# 3066MNPIRH register map
File version: 1.0
Registers are 32-bit, access per field, reset 0x0 unless marked. A register's access mark holds for its fields unless they carry their own. Offsets are from the block's base; [hi:lo] are bit positions; {n}, {i} and the like mark numbered series.

## APT0 — APT0 peripheral interface
Base 0x14A00000
Same registers: APT{n} {0x14A00000+0x1000*n} (n=1..8)
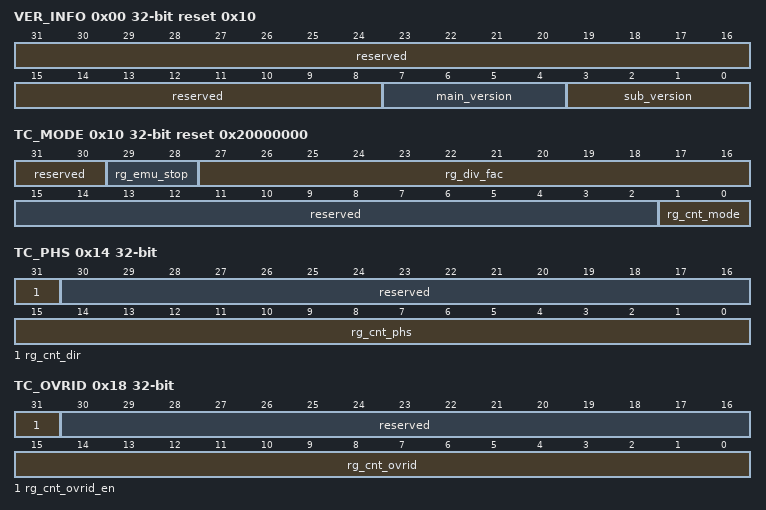
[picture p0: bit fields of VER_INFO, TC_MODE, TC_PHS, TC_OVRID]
0x00 VER_INFO ro reset 0x10 — VER_INFO为版本信息寄存器。
  [31:8] reserved — 保留。
  [7:4] main_version — 主版本号。
  [3:0] sub_version — 子版本号。
0x10 TC_MODE reset 0x20000000 — TC_MODE为计数模式寄存器。
  [31:30] reserved ro — 保留。
  [29:28] rg_emu_stop rw — CPU debug模式，APT停止的方式。注意，如果停止APT，那么在CPU debug模式下，整个APT都会停止工作，包括输出控制功能。 0X：不停止； 10：停止分频计数器（DIVCNT）和时基计数器（TCCNT）； 11：停止APT。
  [27:16] rg_div_fac rw — 分频系数。 分频倍数 = 分频系数 +1。
  [15:2] reserved ro — 保留。
  [1:0] rg_cnt_mode rw — 时基计数器（TCCNT）的工作模式。 00：递增计数； 01：递减计数； 10：先增后减计数； 11：冻结。
0x14 TC_PHS — TC_PHS为计数相位控制寄存器。
  [31] rg_cnt_dir rw — 当APTCNTSYNC有效时，更新时基计数器（TCCNT）的计数方向，仅在先增后减计数模式有效。 0：递减； 1：递增。
  [30:16] reserved ro — 保留。
  [15:0] rg_cnt_phs rw — 当APTCNTSYNC有效时，更新时基计数器（TCCNT）的计数值。
0x18 TC_OVRID — TC_OVRID为计数器初始化寄存器。
  [31] rg_cnt_ovrid_en rw write-1-clears — 时基计数器（TCCNT）和分频计数器（DIVCNT）的初始化使能。 0：无效； 1：初始化时基计数器（TCCNT）和分频计数器（DIVCNT）的计数值。
  [30:16] reserved ro — 保留。
  [15:0] rg_cnt_ovrid rw — 初始化时基计数器（TCCNT）的计数值。
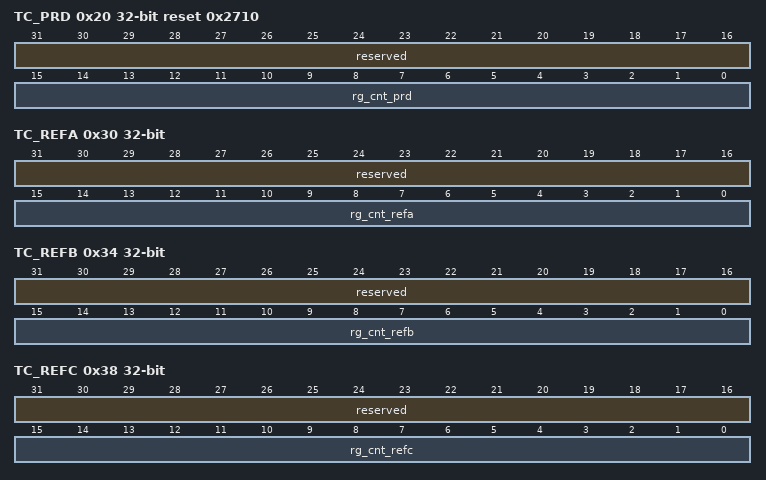
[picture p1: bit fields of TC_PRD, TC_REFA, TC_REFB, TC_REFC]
0x20 TC_PRD reset 0x2710 — TC_PRD为计数周期寄存器。
  [31:16] reserved ro — 保留。
  [15:0] rg_cnt_prd rw — 时基计数器（TCCNT）的计数周期。
0x30 TC_REFA — TC_REFA为计数参考值A寄存器。
  [31:16] reserved ro — 保留。
  [15:0] rg_cnt_refa rw — 时基计数器（TCCNT）的参考值A，应当小于或等于计数周期。
0x34 TC_REFB — TC_REFB为计数参考值B寄存器。
  [31:16] reserved ro — 保留。
  [15:0] rg_cnt_refb rw — 时基计数器（TCCNT）的参考值B，应当小于或等于计数周期。
0x38 TC_REFC — TC_REFC为计数参考值C寄存器。
  [31:16] reserved ro — 保留。
  [15:0] rg_cnt_refc rw — 时基计数器（TCCNT）的参考值C，应当小于或等于计数周期。
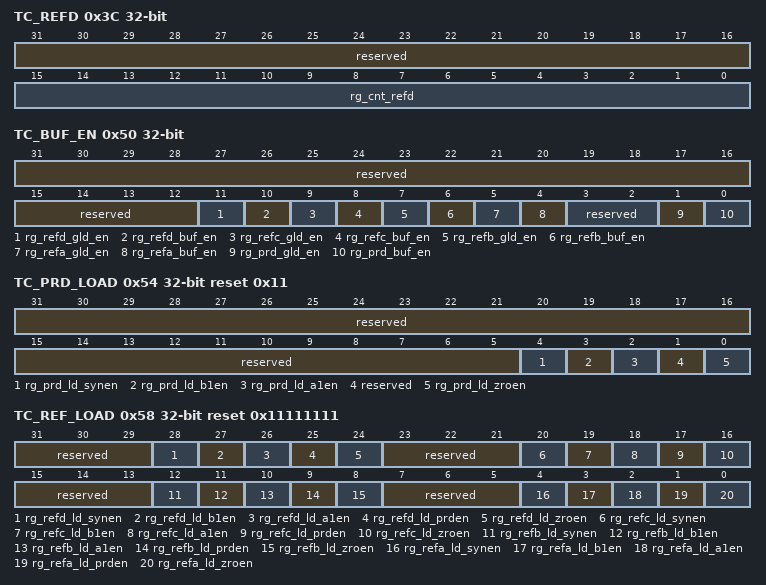
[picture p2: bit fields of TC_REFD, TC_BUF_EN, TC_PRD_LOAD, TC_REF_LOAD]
0x3C TC_REFD — TC_REFD为计数参考值D寄存器。
  [31:16] reserved ro — 保留。
  [15:0] rg_cnt_refd rw — 时基计数器（TCCNT）的参考值D，应当小于或等于计数周期。
0x50 TC_BUF_EN — TC_BUF_EN为计数器缓存使能寄存器。
  [31:12] reserved ro — 保留。
  [11] rg_refd_gld_en rw — TC_REFD寄存器的全局加载使能。 0：不使能； 1：使能。
  [10] rg_refd_buf_en rw — TC_REFD寄存器的缓存使能。 0：不使能； 1：使能。
  [9] rg_refc_gld_en rw — TC_REFC寄存器的全局加载使能。 0：不使能； 1：使能。
  [8] rg_refc_buf_en rw — TC_REFC寄存器的缓存使能。 0：不使能； 1：使能。
  [7] rg_refb_gld_en rw — TC_REFB寄存器的全局加载使能。 0：不使能； 1：使能。
  [6] rg_refb_buf_en rw — TC_REFB寄存器的缓存使能。 0：不使能； 1：使能。
  [5] rg_refa_gld_en rw — TC_REFA寄存器的全局加载使能。 0：不使能； 1：使能。
  [4] rg_refa_buf_en rw — TC_REFA寄存器的缓存使能。 0：不使能； 1：使能。
  [3:2] reserved ro — 保留。
  [1] rg_prd_gld_en rw — TC_PRD寄存器的全局加载使能。 0：不使能； 1：使能。
  [0] rg_prd_buf_en rw — TC_PRD寄存器的缓存使能。 0：不使能； 1：使能。
0x54 TC_PRD_LOAD reset 0x11 — TC_PRD_LOAD为计数周期寄存器独立加载触发信号选择寄存器。
  [31:5] reserved ro — 保留。
  [4] rg_prd_ld_synen rw — 选择APTxSYNCI有效时，是否使能TC_PRD寄存器的独立加载。 0：不使能； 1：使能。
  [3] rg_prd_ld_b1en rw — 选择EMEVTB1有效时，是否使能TC_PRD寄存器的独立加载。 0：不使能； 1：使能。
  [2] rg_prd_ld_a1en rw — 选择EMEVTA1有效时，是否使能TC_PRD寄存器的独立加载。 0：不使能； 1：使能。
  [1] reserved ro — 保留。
  [0] rg_prd_ld_zroen rw — 选择CNT_ZERO有效时，是否使能TC_PRD寄存器的独立加载。 0：不使能； 1：使能。
0x58 TC_REF_LOAD reset 0x11111111 — TC_REF_LOAD为计数参考值寄存器独立加载触发信号选择寄存器。
  [31:29] reserved ro — 保留。
  [28] rg_refd_ld_synen rw — 选择APTxSYNCI有效时，是否使能TC_REFD寄存器的独立加载。 0：不使能； 1：使能。
  [27] rg_refd_ld_b1en rw — 选择EMEVTB1有效时，是否使能TC_REFD寄存器的独立加载。 0：不使能； 1：使能。
  [26] rg_refd_ld_a1en rw — 选择EMEVTA1有效时，是否使能TC_REFD寄存器的独立加载。 0：不使能； 1：使能。
  [25] rg_refd_ld_prden rw — 选择CNT_PRD有效时，是否使能TC_REFD寄存器的独立加载。 0：不使能； 1：使能。
  [24] rg_refd_ld_zroen rw — 选择CNT_ZERO有效时，是否使能TC_REFD寄存器的独立加载。 0：不使能； 1：使能。
  [23:21] reserved ro — 保留。
  [20] rg_refc_ld_synen rw — 选择APTxSYNCI有效时，是否使能TC_REFC寄存器的独立加载。 0：不使能； 1：使能。
  [19] rg_refc_ld_b1en rw — 选择EMEVTB1有效时，是否使能TC_REFC寄存器的独立加载。 0：不使能； 1：使能。
  [18] rg_refc_ld_a1en rw — 选择EMEVTA1有效时，是否使能TC_REFC寄存器的独立加载。 0：不使能； 1：使能。
  [17] rg_refc_ld_prden rw — 选择CNT_PRD有效时，是否使能TC_REFC寄存器的独立加载。 0：不使能； 1：使能。
  [16] rg_refc_ld_zroen rw — 选择CNT_ZERO有效时，是否使能TC_REFC寄存器的独立加载。 0：不使能； 1：使能。
  [15:13] reserved ro — 保留。
  [12] rg_refb_ld_synen rw — 选择APTxSYNCI有效时，是否使能TC_REFB寄存器的独立加载。 0：不使能； 1：使能。
  [11] rg_refb_ld_b1en rw — 选择EMEVTB1有效时，是否使能TC_REFB寄存器的独立加载。 0：不使能； 1：使能。
  [10] rg_refb_ld_a1en rw — 选择EMEVTA1有效时，是否使能TC_REFB寄存器的独立加载。 0：不使能； 1：使能。
  [9] rg_refb_ld_prden rw — 选择CNT_PRD有效时，是否使能TC_REFB寄存器的独立加载。 0：不使能； 1：使能。
  [8] rg_refb_ld_zroen rw — 选择CNT_ZERO有效时，是否使能TC_REFB寄存器的独立加载。 0：不使能； 1：使能。
  [7:5] reserved ro — 保留。
  [4] rg_refa_ld_synen rw — 选择APTxSYNCI有效时，是否使能TC_REFA寄存器的独立加载。 0：不使能； 1：使能。
  [3] rg_refa_ld_b1en rw — 选择EMEVTB1有效时，是否使能TC_REFA寄存器的独立加载。 0：不使能； 1：使能。
  [2] rg_refa_ld_a1en rw — 选择EMEVTA1有效时，是否使能TC_REFA寄存器的独立加载。 0：不使能； 1：使能。
  [1] rg_refa_ld_prden rw — 选择CNT_PRD有效时，是否使能TC_REFA寄存器的独立加载。 0：不使能； 1：使能。
  [0] rg_refa_ld_zroen rw — 选择CNT_ZERO有效时，是否使能TC_REFA寄存器的独立加载。 0：不使能； 1：使能。
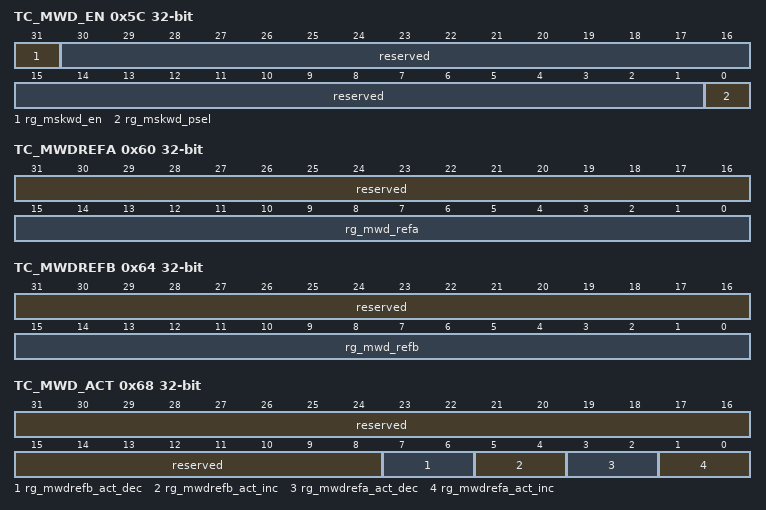
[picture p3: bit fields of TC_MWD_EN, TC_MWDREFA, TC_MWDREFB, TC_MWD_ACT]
0x5C TC_MWD_EN — TC_MWD_EN为屏蔽窗口使能寄存器。
  [31] rg_mskwd_en rw — 屏蔽窗口使能位。 0：不使能； 1：使能。
  [30:1] reserved ro — 保留。
  [0] rg_mskwd_psel rw — MASK_WD_POL的源选择。 0：MASK_WD_POL的源是MASK_WD取反后的波形； 1：MASK_WD_POL的源是MASK_WD。
0x60 TC_MWDREFA — TC_MWDREFA为屏蔽窗口参考值A寄存器。
  [31:16] reserved ro — 保留。
  [15:0] rg_mwd_refa rw — 屏蔽窗口参考值A，应当小于或等于计数周期。
0x64 TC_MWDREFB — TC_MWDREFB为屏蔽窗口参考值B寄存器。
  [31:16] reserved ro — 保留。
  [15:0] rg_mwd_refb rw — 屏蔽窗口参考值B，应当小于或等于计数周期。
0x68 TC_MWD_ACT — TC_MWD_ACT为MASK_WD动作寄存器。
  [31:8] reserved ro — 保留。
  [7:6] rg_mwdrefb_act_dec rw — CNT_MWDREFB有效且TCCNT计数方向递减时，MASK_WD的动作。 00：无影响； 01：置为低电平； 10：置为高电平； 11：翻转电平。
  [5:4] rg_mwdrefb_act_inc rw — CNT_MWDREFB有效且TCCNT计数方向递增时，MASK_WD的动作。 00：无影响； 01：置为低电平； 10：置为高电平； 11：翻转电平。
  [3:2] rg_mwdrefa_act_dec rw — CNT_MWDREFA有效且TCCNT计数方向递减时，MASK_WD的动作。 00：无影响； 01：置为低电平； 10：置为高电平； 11：翻转电平。
  [1:0] rg_mwdrefa_act_inc rw — CNT_MWDREFA有效且TCCNT计数方向递增时，MASK_WD的动作。 00：无影响； 01：置为低电平； 10：置为高电平； 11：翻转电平。
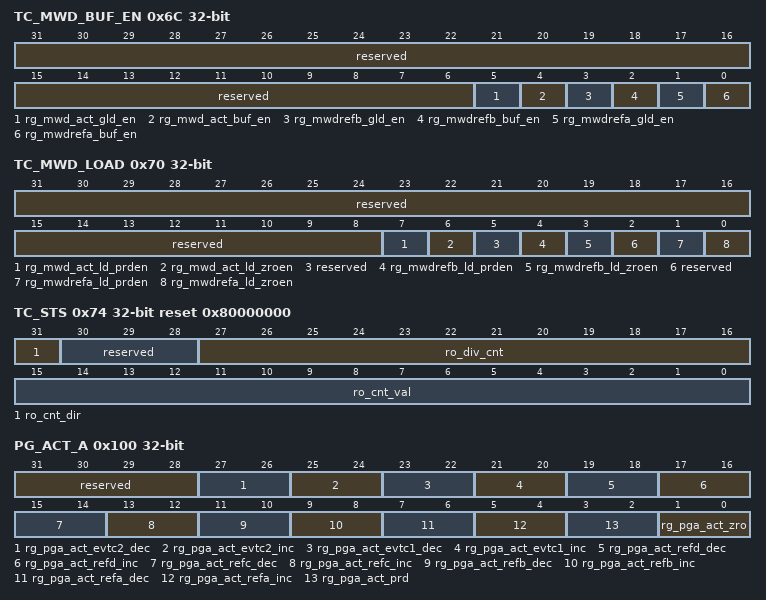
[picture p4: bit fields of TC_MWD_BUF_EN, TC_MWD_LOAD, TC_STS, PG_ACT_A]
0x6C TC_MWD_BUF_EN — TC_MWD_BUF_EN为屏蔽窗口缓存使能寄存器。
  [31:6] reserved ro — 保留。
  [5] rg_mwd_act_gld_en rw — TC_MWD_ACT寄存器的全局加载使能。 0：不使能； 1：使能。
  [4] rg_mwd_act_buf_en rw — TC_MWD_ACT寄存器的缓存使能。 0：不使能； 1：使能。
  [3] rg_mwdrefb_gld_en rw — TC_MWDREFB寄存器的全局加载使能。 0：不使能； 1：使能。
  [2] rg_mwdrefb_buf_en rw — TC_MWDREFB寄存器的缓存使能。 0：不使能； 1：使能。
  [1] rg_mwdrefa_gld_en rw — TC_MWDREFA寄存器的全局加载使能。 0：不使能； 1：使能。
  [0] rg_mwdrefa_buf_en rw — TC_MWDREFA寄存器的缓存使能。 0：不使能； 1：使能。
0x70 TC_MWD_LOAD — TC_MWD_LOAD为屏蔽窗口寄存器独立加载触发信号选择寄存器。
  [31:8] reserved ro — 保留。
  [7] rg_mwd_act_ld_prden rw — 选择CNT_PRD有效时，是否使能TC_MWD_ACT寄存器的独立加载。 0：不使能； 1：使能。
  [6] rg_mwd_act_ld_zroen rw — 选择CNT_ZERO有效时，是否使能TC_MWD_ACT寄存器的独立加载。 0：不使能； 1：使能。
  [5] reserved ro — 保留。
  [4] rg_mwdrefb_ld_prden rw — 选择CNT_PRD有效时，是否使能TC_MWDREFB寄存器的独立加载。 0：不使能； 1：使能。
  [3] rg_mwdrefb_ld_zroen rw — 选择CNT_ZERO有效时，是否使能TC_MWDREFB寄存器的独立加载。 0：不使能； 1：使能。
  [2] reserved ro — 保留。
  [1] rg_mwdrefa_ld_prden rw — 选择CNT_PRD有效时，是否使能TC_MWDREFA寄存器的独立加载。 0：不使能； 1：使能。
  [0] rg_mwdrefa_ld_zroen rw — 选择CNT_ZERO有效时，是否使能TC_MWDREFA寄存器的独立加载。 0：不使能； 1：使能。
0x74 TC_STS ro reset 0x80000000 — TC_STS为计数状态寄存器。
  [31] ro_cnt_dir — 时基计数器（TCCNT）的当前计数方向。 0：递减计数； 1：递增计数。
  [30:28] reserved — 保留。
  [27:16] ro_div_cnt — 分频计数器（DIVCNT）的当前计数值。
  [15:0] ro_cnt_val — 时基计数器（TCCNT）的当前计数值。
0x100 PG_ACT_A — PG_ACT_A为PG_PWMA动作配置寄存器。
  [31:28] reserved ro — 保留。
  [27:26] rg_pga_act_evtc2_dec rw — AEVTC2有效且TCCNT计数方向递减时，PG_PWMA的动作。 00：无影响； 01：置为低电平； 10：置为高电平； 11：翻转电平。
  [25:24] rg_pga_act_evtc2_inc rw — AEVTC2有效且TCCNT计数方向递增时，PG_PWMA的动作。 00：无影响； 01：置为低电平； 10：置为高电平； 11：翻转电平。
  [23:22] rg_pga_act_evtc1_dec rw — AEVTC1有效且TCCNT计数方向递减时，PG_PWMA的动作。 00：无影响； 01：置为低电平； 10：置为高电平； 11：翻转电平。
  [21:20] rg_pga_act_evtc1_inc rw — AEVTC1有效且TCCNT计数方向递增时，PG_PWMA的动作。 00：无影响； 01：置为低电平； 10：置为高电平； 11：翻转电平。
  [19:18] rg_pga_act_refd_dec rw — CNT_REFD有效且TCCNT计数方向递减时，PG_PWMA的动作。 00：无影响； 01：置为低电平； 10：置为高电平； 11：翻转电平。
  [17:16] rg_pga_act_refd_inc rw — CNT_REFD有效且TCCNT计数方向递增时，PG_PWMA的动作。 00：无影响； 01：置为低电平； 10：置为高电平； 11：翻转电平。
  [15:14] rg_pga_act_refc_dec rw — CNT_REFC有效且TCCNT计数方向递减时，PG_PWMA的动作。 00：无影响； 01：置为低电平； 10：置为高电平； 11：翻转电平。
  [13:12] rg_pga_act_refc_inc rw — CNT_REFC有效且TCCNT计数方向递增时，PG_PWMA的动作。 00：无影响； 01：置为低电平； 10：置为高电平； 11：翻转电平。
  [11:10] rg_pga_act_refb_dec rw — CNT_REFB有效且TCCNT计数方向递减时，PG_PWMA的动作。 00：无影响； 01：置为低电平； 10：置为高电平； 11：翻转电平。
  [9:8] rg_pga_act_refb_inc rw — CNT_REFB有效且TCCNT计数方向递增时，PG_PWMA的动作。 00：无影响； 01：置为低电平； 10：置为高电平； 11：翻转电平。
  [7:6] rg_pga_act_refa_dec rw — CNT_REFA有效且TCCNT计数方向递减时，PG_PWMA的动作。 00：无影响； 01：置为低电平； 10：置为高电平； 11：翻转电平。
  [5:4] rg_pga_act_refa_inc rw — CNT_REFA有效且TCCNT计数方向递增时，PG_PWMA的动作。 00：无影响； 01：置为低电平； 10：置为高电平； 11：翻转电平。
  [3:2] rg_pga_act_prd rw — CNT_PRD有效时，PG_PWMA的动作。 00：无影响； 01：置为低电平； 10：置为高电平； 11：翻转电平。
  [1:0] rg_pga_act_zro rw — CNT_ZERO有效时，PG_PWMA的动作。 00：无影响； 01：置为低电平； 10：置为高电平； 11：翻转电平。
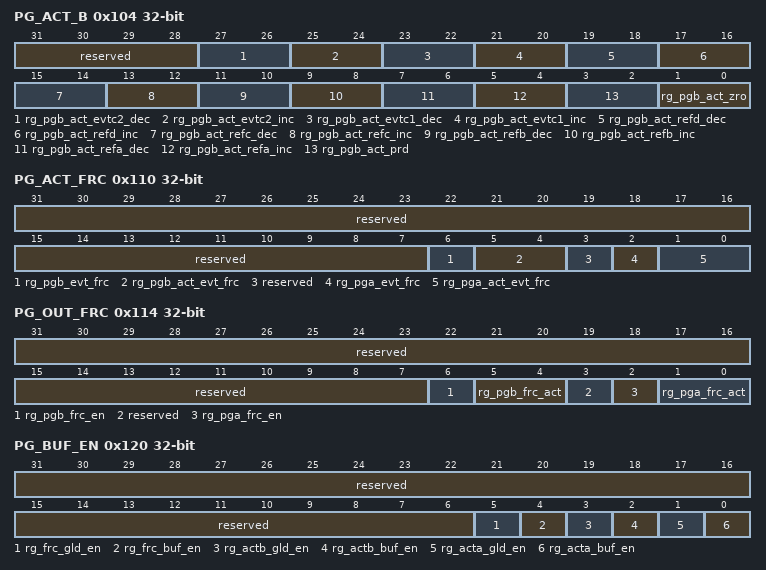
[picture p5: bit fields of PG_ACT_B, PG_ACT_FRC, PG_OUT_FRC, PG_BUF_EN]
0x104 PG_ACT_B — PG_ACT_B为PG_PWMB动作配置寄存器。
  [31:28] reserved ro — 保留。
  [27:26] rg_pgb_act_evtc2_dec rw — BEVTC2有效且TCCNT计数方向递减时，PG_PWMB的动作。 00：无影响； 01：置为低电平； 10：置为高电平； 11：翻转电平。
  [25:24] rg_pgb_act_evtc2_inc rw — BEVTC2有效且TCCNT计数方向递增时，PG_PWMB的动作。 00：无影响； 01：置为低电平； 10：置为高电平； 11：翻转电平。
  [23:22] rg_pgb_act_evtc1_dec rw — BEVTC1有效且TCCNT计数方向递减时，PG_PWMB的动作。 00：无影响； 01：置为低电平； 10：置为高电平； 11：翻转电平。
  [21:20] rg_pgb_act_evtc1_inc rw — BEVTC1有效且TCCNT计数方向递增时，PG_PWMB的动作。 00：无影响； 01：置为低电平； 10：置为高电平； 11：翻转电平。
  [19:18] rg_pgb_act_refd_dec rw — CNT_REFD有效且TCCNT计数方向递减时，PG_PWMB的动作。 00：无影响； 01：置为低电平； 10：置为高电平； 11：翻转电平。
  [17:16] rg_pgb_act_refd_inc rw — CNT_REFD有效且TCCNT计数方向递增时，PG_PWMB的动作。 00：无影响； 01：置为低电平； 10：置为高电平； 11：翻转电平。
  [15:14] rg_pgb_act_refc_dec rw — CNT_REFC有效且TCCNT计数方向递减时，PG_PWMB的动作。 00：无影响； 01：置为低电平； 10：置为高电平； 11：翻转电平。
  [13:12] rg_pgb_act_refc_inc rw — CNT_REFC有效且TCCNT计数方向递增时，PG_PWMB的动作。 00：无影响； 01：置为低电平； 10：置为高电平； 11：翻转电平。
  [11:10] rg_pgb_act_refb_dec rw — CNT_REFB有效且TCCNT计数方向递减时，PG_PWMB的动作。 00：无影响； 01：置为低电平； 10：置为高电平； 11：翻转电平。
  [9:8] rg_pgb_act_refb_inc rw — CNT_REFB有效且TCCNT计数方向递增时，PG_PWMB的动作。 00：无影响； 01：置为低电平； 10：置为高电平； 11：翻转电平。
  [7:6] rg_pgb_act_refa_dec rw — CNT_REFA有效且TCCNT计数方向递减时，PG_PWMB的动作。 00：无影响； 01：置为低电平； 10：置为高电平； 11：翻转电平。
  [5:4] rg_pgb_act_refa_inc rw — CNT_REFA有效且TCCNT计数方向递增时，PG_PWMB的动作。 00：无影响； 01：置为低电平； 10：置为高电平； 11：翻转电平。
  [3:2] rg_pgb_act_prd rw — CNT_PRD有效时，PG_PWMB的动作。 00：无影响； 01：置为低电平； 10：置为高电平； 11：翻转电平。
  [1:0] rg_pgb_act_zro rw — CNT_ZERO有效时，PG_PWMB的动作。 00：无影响； 01：置为低电平； 10：置为高电平； 11：翻转电平。
0x110 PG_ACT_FRC — PG_ACT_FRC为强制动作配置寄存器。
  [31:7] reserved ro — 保留。
  [6] rg_pgb_evt_frc rw write-1-clears — 软件强制PG_PWMB动作，每次写1产生一次PG_PWMB动作，然后自动清零。 0：写0无效； 1：写1有效。
  [5:4] rg_pgb_act_evt_frc rw — 软件强制PG_PWMB动作有效时，PG_PWMB的动作。 00：无影响； 01：置为低电平； 10：置为高电平； 11：翻转电平。
  [3] reserved ro — 保留。
  [2] rg_pga_evt_frc rw write-1-clears — 软件强制PG_PWMA动作，每次写1产生一次PG_PWMA动作，然后自动清零。 0：写0无效； 1：写1有效。
  [1:0] rg_pga_act_evt_frc rw — 软件强制PG_PWMA动作有效时，PG_PWMA的动作。 00：无影响； 01：置为低电平； 10：置为高电平； 11：翻转电平。
0x114 PG_OUT_FRC — PG_OUT_FRC为强制输出配置寄存器。
  [31:7] reserved ro — 保留。
  [6] rg_pgb_frc_en rw — PG_PWMB软件强制输出使能。 0：不使能； 1：使能。
  [5:4] rg_pgb_frc_act rw — PG_PWMB软件强制输出使能时，PG_PWMB的输出状态。 00：锁定电平； 01：置为低电平； 10：置为高电平； 11：保留。
  [3] reserved ro — 保留。
  [2] rg_pga_frc_en rw — PG_PWMA软件强制输出使能。 0：不使能； 1：使能。
  [1:0] rg_pga_frc_act rw — PG_PWMA软件强制输出使能时，PG_PWMA的输出状态。 00：锁定电平； 01：置为低电平； 10：置为高电平； 11：保留。
0x120 PG_BUF_EN — PG_BUF_EN为波形生成缓存使能寄存器。
  [31:6] reserved ro — 保留。
  [5] rg_frc_gld_en rw — PG_OUT_FRC寄存器的全局加载使能。 0：不使能； 1：使能。
  [4] rg_frc_buf_en rw — PG_OUT_FRC寄存器的缓存使能。 0：不使能； 1：使能。
  [3] rg_actb_gld_en rw — PG_ACT_B寄存器的全局加载使能。 0：不使能； 1：使能。
  [2] rg_actb_buf_en rw — PG_ACT_B寄存器的缓存使能。 0：不使能； 1：使能。
  [1] rg_acta_gld_en rw — PG_ACT_A寄存器的全局加载使能。 0：不使能； 1：使能。
  [0] rg_acta_buf_en rw — PG_ACT_A寄存器的缓存使能。 0：不使能； 1：使能。
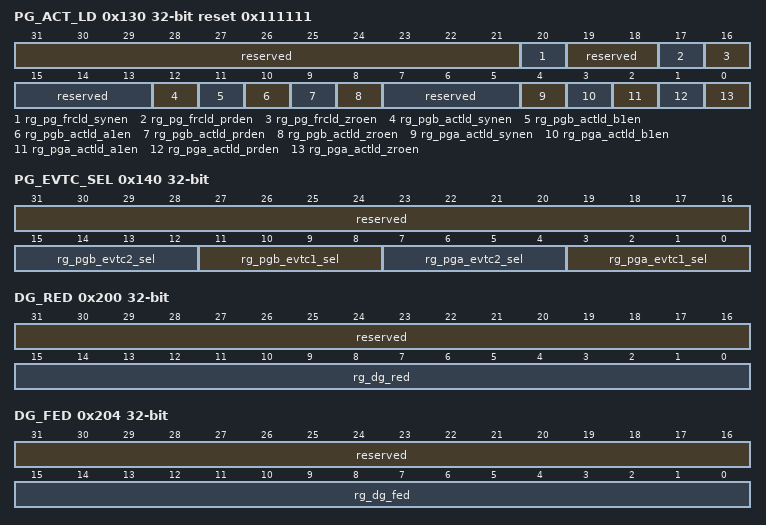
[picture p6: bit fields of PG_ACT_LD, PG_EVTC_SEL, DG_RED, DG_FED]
0x130 PG_ACT_LD reset 0x111111 — PG_ACT_LD为波形生成动作独立加载触发信号选择寄存器。
  [31:21] reserved ro — 保留。
  [20] rg_pg_frcld_synen rw — 选择APTxSYNCI有效时，是否使能PG_OUT_FRC寄存器的独立加载。 0：不使能； 1：使能。
  [19:18] reserved ro — 保留。
  [17] rg_pg_frcld_prden rw — 选择CNT_PRD有效时，是否使能PG_OUT_FRC寄存器的独立加载。 0：不使能； 1：使能。
  [16] rg_pg_frcld_zroen rw — 选择CNT_ZERO有效时，是否使能PG_OUT_FRC寄存器的独立加载。 0：不使能； 1：使能。
  [15:13] reserved ro — 保留。
  [12] rg_pgb_actld_synen rw — 选择APTxSYNCI有效时，是否使能PG_ACT_B寄存器的独立加载。 0：不使能； 1：使能。
  [11] rg_pgb_actld_b1en rw — 选择EMEVTB1有效时，是否使能PG_ACT_B寄存器的独立加载。 0：不使能； 1：使能。
  [10] rg_pgb_actld_a1en rw — 选择EMEVTA1有效时，是否使能PG_ACT_B寄存器的独立加载。 0：不使能； 1：使能。
  [9] rg_pgb_actld_prden rw — 选择CNT_PRD有效时，是否使能PG_ACT_B寄存器的独立加载。 0：不使能； 1：使能。
  [8] rg_pgb_actld_zroen rw — 选择CNT_ZERO有效时，是否使能PG_ACT_B寄存器的独立加载。 0：不使能； 1：使能。
  [7:5] reserved ro — 保留。
  [4] rg_pga_actld_synen rw — 选择APTxSYNCI有效时，是否使能PG_ACT_A寄存器的独立加载。 0：不使能； 1：使能。
  [3] rg_pga_actld_b1en rw — 选择EMEVTB1有效时，是否使能PG_ACT_A寄存器的独立加载。 0：不使能； 1：使能。
  [2] rg_pga_actld_a1en rw — 选择EMEVTA1有效时，是否使能PG_ACT_A寄存器的独立加载。 0：不使能； 1：使能。
  [1] rg_pga_actld_prden rw — 选择CNT_PRD有效时，是否使能PG_ACT_A寄存器的独立加载。 0：不使能； 1：使能。
  [0] rg_pga_actld_zroen rw — 选择CNT_ZERO有效时，是否使能PG_ACT_A寄存器的独立加载。 0：不使能； 1：使能。
0x140 PG_EVTC_SEL — PG_EVTC_SEL为波形生成事件C触发源选择寄存器。
  [31:16] reserved ro — 保留。
  [15:12] rg_pgb_evtc2_sel rw — BEVTC2触发源选择。 0x1：EMEVTA1_TEMP； 0x2：EMEVTA2_TEMP； 0x3：EMEVTB1_TEMP； 0x4：EMEVTB2_TEMP； 0x5：EMEVTFILT； 0x6：TRIP1； 0x7：TRIP2； 0x8：TRIP3； 0x9：APTxSYNCI； 其他：禁止产生BEVTC2。
  [11:8] rg_pgb_evtc1_sel rw — BEVTC1触发源选择。 0x1：EMEVTA1_TEMP； 0x2：EMEVTA2_TEMP； 0x3：EMEVTB1_TEMP； 0x4：EMEVTB2_TEMP； 0x5：EMEVTFILT； 0x6：TRIP1； 0x7：TRIP2； 0x8：TRIP3； 0x9：APTxSYNCI； 其他：禁止产生BEVTC1。
  [7:4] rg_pga_evtc2_sel rw — AEVTC2触发源选择。 0x1：EMEVTA1_TEMP； 0x2：EMEVTA2_TEMP； 0x3：EMEVTB1_TEMP； 0x4：EMEVTB2_TEMP； 0x5：EMEVTFILT； 0x6：TRIP1； 0x7：TRIP2； 0x8：TRIP3； 0x9：APTxSYNCI； 其他：禁止产生AEVTC2。
  [3:0] rg_pga_evtc1_sel rw — AEVTC1触发源选择。 0x1：EMEVTA1_TEMP； 0x2：EMEVTA2_TEMP； 0x3：EMEVTB1_TEMP； 0x4：EMEVTB2_TEMP； 0x5：EMEVTFILT； 0x6：TRIP1； 0x7：TRIP2； 0x8：TRIP3； 0x9：APTxSYNCI； 其他：禁止产生AEVTC1。
0x200 DG_RED — DG_RED为死区上升沿延时配置寄存器。
  [31:16] reserved ro — 保留。
  [15:0] rg_dg_red rw — 死区上升沿延时配置。
0x204 DG_FED — DG_FED为死区下降沿延时配置寄存器。
  [31:16] reserved ro — 保留。
  [15:0] rg_dg_fed rw — 死区下降沿延时配置。
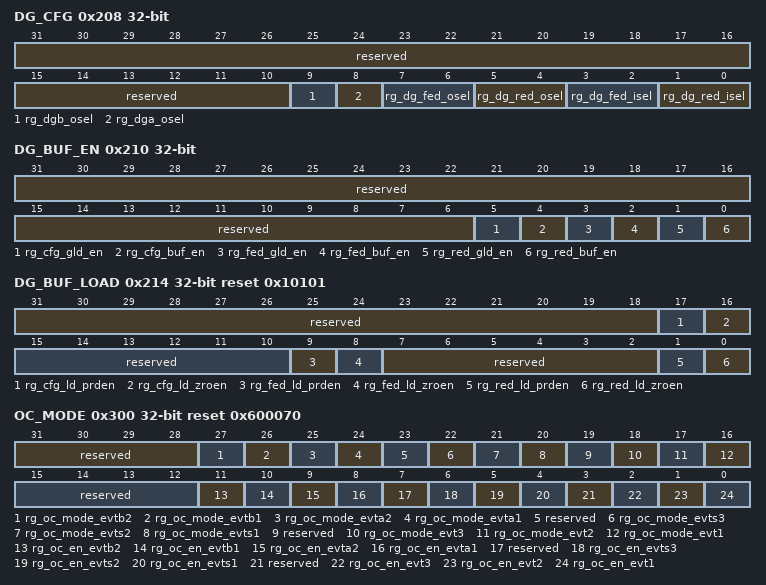
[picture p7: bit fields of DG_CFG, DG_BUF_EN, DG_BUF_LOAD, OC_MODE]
0x208 DG_CFG — DG_CFG为死区配置寄存器。
  [31:10] reserved ro — 保留。
  [9] rg_dgb_osel rw — 选择DG_PWMB的源。 0：选择PWM_FED_POL作为DG_PWMB； 1：选择PWM_RED_POL作为DG_PWMB。
  [8] rg_dga_osel rw — 选择DG_PWMA的源。 0：选择PWM_RED_POL作为DG_PWMA； 1：选择PWM_FED_POL作为DG_PWMA。
  [7:6] rg_dg_fed_osel rw — 选择PWM_FED_POL的源。 0X：选择PWM_FED_AFTER作为PWM_FED_POL； 10：选择PWM_FED_AFTER取反后作为PWM_FED_POL； 11：选择PG_PWMB作为PWM_FED_POL。
  [5:4] rg_dg_red_osel rw — 选择PWM_RED_POL的源。 0X：选择PWM_RED_AFTER作为PWM_RED_POL； 10：选择PWM_RED_AFTER取反后作为PWM_RED_POL； 11：选择PG_PWMA作为PWM_RED_POL。
  [3:2] rg_dg_fed_isel rw — 选择PWM_FED_BEFORE的源。 00：选择PG_PWMB作为PWM_FED_BEFORE； 01：选择PG_PWMA作为PWM_FED_BEFORE； 10：选择PWM_RED_BEFORE作为PWM_FED_BEFORE； 11：将PWM_FED_BEFORE固定为低电平。
  [1:0] rg_dg_red_isel rw — 选择PWM_RED_BEFORE的源。 X0：选择PG_PWMA作为PWM_RED_BEFORE； X1：选择PG_PWMB作为PWM_RED_BEFORE。
0x210 DG_BUF_EN — DG_BUF_EN为死区生成缓存使能寄存器。
  [31:6] reserved ro — 保留。
  [5] rg_cfg_gld_en rw — DG_CFG寄存器的全局加载使能。 0：不使能； 1：使能。
  [4] rg_cfg_buf_en rw — DG_CFG寄存器的缓存使能。 0：不使能； 1：使能。
  [3] rg_fed_gld_en rw — DG_CFG寄存器的全局加载使能。 0：不使能； 1：使能。
  [2] rg_fed_buf_en rw — DG_FED寄存器的缓存使能。 0：不使能； 1：使能。
  [1] rg_red_gld_en rw — DG_RED寄存器的全局加载使能。 0：不使能； 1：使能。
  [0] rg_red_buf_en rw — DG_RED寄存器的缓存使能。 0：不使能； 1：使能。
0x214 DG_BUF_LOAD reset 0x10101 — DG_BUF_LOAD为死区生成独立加载触发信号选择寄存器。
  [31:18] reserved ro — 保留。
  [17] rg_cfg_ld_prden rw — 选择CNT_PRD有效时，是否使能DG_CFG寄存器的独立加载。 0：不使能； 1：使能。
  [16] rg_cfg_ld_zroen rw — 选择CNT_ZERO有效时，是否使能DG_CFG寄存器的独立加载。 0：不使能； 1：使能。
  [15:10] reserved ro — 保留。
  [9] rg_fed_ld_prden rw — 选择CNT_PRD有效时，是否使能DG_FED寄存器的独立加载。 0：不使能； 1：使能。
  [8] rg_fed_ld_zroen rw — 选择CNT_ZERO有效时，是否使能DG_FED寄存器的独立加载。 0：不使能； 1：使能。
  [7:2] reserved ro — 保留。
  [1] rg_red_ld_prden rw — 选择CNT_PRD有效时，是否使能DG_RED寄存器的独立加载。 0：不使能； 1：使能。
  [0] rg_red_ld_zroen rw — 选择CNT_ZERO有效时，是否使能DG_RED寄存器的独立加载。 0：不使能； 1：使能。
0x300 OC_MODE reset 0x600070 — OC_MODE为输出保护模式寄存器。
  [31:28] reserved ro — 保留。
  [27] rg_oc_mode_evtb2 rw — EMEVTB2的输出保护模式选择。 0：持续性保护； 1：周期性保护。
  [26] rg_oc_mode_evtb1 rw — EMEVTB1的输出保护模式选择。 0：持续性保护； 1：周期性保护。
  [25] rg_oc_mode_evta2 rw — EMEVTA2的输出保护模式选择。 0：持续性保护； 1：周期性保护。
  [24] rg_oc_mode_evta1 rw — EMEVTA1的输出保护模式选择。 0：持续性保护； 1：周期性保护。
  [23] reserved ro — 保留。
  [22] rg_oc_mode_evts3 rw — TRIP11的输出保护模式选择。 0：持续性保护； 1：周期性保护。
  [21] rg_oc_mode_evts2 rw — TRIP10的输出保护模式选择。 0：持续性保护； 1：周期性保护。
  [20] rg_oc_mode_evts1 rw — TRIP9的输出保护模式选择。 0：持续性保护； 1：周期性保护。
  [19] reserved ro — 保留。
  [18] rg_oc_mode_evt3 rw — TRIP3的输出保护模式选择。 0：持续性保护； 1：周期性保护。
  [17] rg_oc_mode_evt2 rw — TRIP2的输出保护模式选择。 0：持续性保护； 1：周期性保护。
  [16] rg_oc_mode_evt1 rw — TRIP1的输出保护模式选择。 0：持续性保护； 1：周期性保护。
  [15:12] reserved ro — 保留。
  [11] rg_oc_en_evtb2 rw — EMEVTB2的输出保护使能。 0：不使能； 1：使能。
  [10] rg_oc_en_evtb1 rw — EMEVTB1的输出保护使能。 0：不使能； 1：使能。
  [9] rg_oc_en_evta2 rw — EMEVTA2的输出保护使能。 0：不使能； 1：使能。
  [8] rg_oc_en_evta1 rw — EMEVTA1的输出保护使能。 0：不使能； 1：使能。
  [7] reserved ro — 保留。
  [6] rg_oc_en_evts3 rw — TRIP11的输出保护使能。 0：不使能； 1：使能。
  [5] rg_oc_en_evts2 rw — TRIP10的输出保护使能。 0：不使能； 1：使能。
  [4] rg_oc_en_evts1 rw — TRIP9的输出保护使能。 0：不使能； 1：使能。
  [3] reserved ro — 保留。
  [2] rg_oc_en_evt3 rw — TRIP3的输出保护使能。 0：不使能； 1：使能。
  [1] rg_oc_en_evt2 rw — TRIP2的输出保护使能。 0：不使能； 1：使能。
  [0] rg_oc_en_evt1 rw — TRIP1的输出保护使能。 0：不使能； 1：使能。
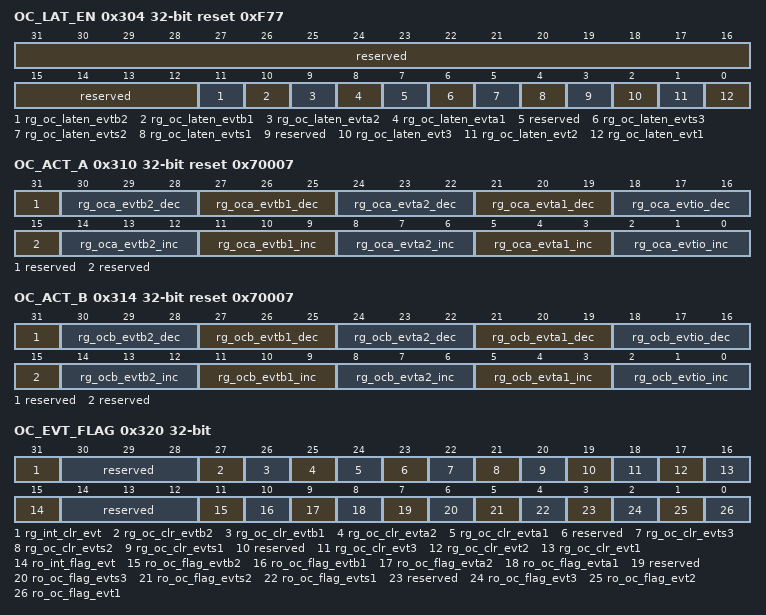
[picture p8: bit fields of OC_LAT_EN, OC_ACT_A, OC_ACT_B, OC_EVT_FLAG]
0x304 OC_LAT_EN reset 0xF77 — OC_LAT_EN为故障信号锁存使能寄存器。
  [31:12] reserved ro — 保留。
  [11] rg_oc_laten_evtb2 rw — EMEVTB2的锁存使能。 0：不使能； 1：使能。
  [10] rg_oc_laten_evtb1 rw — EMEVTB1的锁存使能。 0：不使能； 1：使能。
  [9] rg_oc_laten_evta2 rw — EMEVTA2的锁存使能。 0：不使能； 1：使能。
  [8] rg_oc_laten_evta1 rw — EMEVTA1的锁存使能。 0：不使能； 1：使能。
  [7] reserved ro — 保留。
  [6] rg_oc_laten_evts3 rw — TRIP11的锁存使能。 0：不使能； 1：使能。
  [5] rg_oc_laten_evts2 rw — TRIP10的锁存使能。 0：不使能； 1：使能。
  [4] rg_oc_laten_evts1 rw — TRIP9的锁存使能。 0：不使能； 1：使能。
  [3] reserved ro — 保留。
  [2] rg_oc_laten_evt3 rw — TRIP3的锁存使能。 0：不使能； 1：使能。
  [1] rg_oc_laten_evt2 rw — TRIP2的锁存使能。 0：不使能； 1：使能。
  [0] rg_oc_laten_evt1 rw — TRIP1的锁存使能。 0：不使能； 1：使能。
0x310 OC_ACT_A reset 0x70007 — OC_ACT_A为APTx_PWMA输出保护寄存器。
  [31] reserved ro — 保留。
  [30:28] rg_oca_evtb2_dec rw — EMEVTB2有效且TCCNT计数方向递减时，APTx_PWMA的输出状态。 000：不做任何动作； 001：低电平； 010：高电平； 011：锁定电平； 100：翻转电平； 其他：高阻态。
  [27:25] rg_oca_evtb1_dec rw — EMEVTB1有效且TCCNT计数方向递减时，APTx_PWMA的输出状态。 000：不做任何动作； 001：低电平； 010：高电平； 011：锁定电平； 100：翻转电平； 其他：高阻态。
  [24:22] rg_oca_evta2_dec rw — EMEVTA2有效且TCCNT计数方向递减时，APTx_PWMA的输出状态。 000：不做任何动作； 001：低电平； 010：高电平； 011：锁定电平； 100：翻转电平； 其他：高阻态。
  [21:19] rg_oca_evta1_dec rw — EMEVTA1有效且TCCNT计数方向递减时，APTx_PWMA的输出状态。 000：不做任何动作； 001：低电平； 010：高电平； 011：锁定电平； 100：翻转电平； 其他：高阻态。
  [18:16] rg_oca_evtio_dec rw — TRIP1 ～ TRIP3或TRIP9 ~ TRIP11有效且TCCNT计数方向递减时，APTx_PWMA的输出状态。 000：不做任何动作； 001：低电平； 010：高电平； 011：锁定电平； 100：翻转电平； 其他：高阻态。
  [15] reserved ro — 保留。
  [14:12] rg_oca_evtb2_inc rw — EMEVTB2有效且TCCNT计数方向递增时，APTx_PWMA的输出状态。 000：不做任何动作； 001：低电平； 010：高电平； 011：锁定电平； 100：翻转电平； 其他：高阻态。
  [11:9] rg_oca_evtb1_inc rw — EMEVTB1有效且TCCNT计数方向递增时，APTx_PWMA的输出状态。 000：不做任何动作； 001：低电平； 010：高电平； 011：锁定电平； 100：翻转电平； 其他：高阻态。
  [8:6] rg_oca_evta2_inc rw — EMEVTA2有效且TCCNT计数方向递增时，APTx_PWMA的输出状态。 000：不做任何动作； 001：低电平； 010：高电平； 011：锁定电平； 100：翻转电平； 其他：高阻态。
  [5:3] rg_oca_evta1_inc rw — EMEVTA1有效且TCCNT计数方向递增时，APTx_PWMA的输出状态。 000：不做任何动作； 001：低电平； 010：高电平； 011：锁定电平； 100：翻转电平； 其他：高阻态。
  [2:0] rg_oca_evtio_inc rw — TRIP1 ～ TRIP3或TRIP9 ~ TRIP11有效且TCCNT计数方向递增时，APTx_PWMA的输出状态。 000：不做任何动作； 001：低电平； 010：高电平； 011：锁定电平； 100：翻转电平； 其他：高阻态。
0x314 OC_ACT_B reset 0x70007 — OC_ACT_B为APTx_PWMB输出保护寄存器。
  [31] reserved ro — 保留。
  [30:28] rg_ocb_evtb2_dec rw — EMEVTB2有效且TCCNT计数方向递减时，APTx_PWMB的输出状态。 000：不做任何动作； 001：低电平； 010：高电平； 011：锁定电平； 100：翻转电平； 其他：高阻态。
  [27:25] rg_ocb_evtb1_dec rw — EMEVTB1有效且TCCNT计数方向递减时，APTx_PWMB的输出状态。 000：不做任何动作； 001：低电平； 010：高电平； 011：锁定电平； 100：翻转电平； 其他：高阻态。
  [24:22] rg_ocb_evta2_dec rw — EMEVTA2有效且TCCNT计数方向递减时，APTx_PWMB的输出状态。 000：不做任何动作； 001：低电平； 010：高电平； 011：锁定电平； 100：翻转电平； 其他：高阻态。
  [21:19] rg_ocb_evta1_dec rw — EMEVTA1有效且TCCNT计数方向递减时，APTx_PWMB的输出状态。 000：不做任何动作； 001：低电平； 010：高电平； 011：锁定电平； 100：翻转电平； 其他：高阻态。
  [18:16] rg_ocb_evtio_dec rw — TRIP1 ～ TRIP3或TRIP9 ~ TRIP11有效且TCCNT计数方向递减时，APTx_PWMB的输出状态。 000：不做任何动作； 001：低电平； 010：高电平； 011：锁定电平； 100：翻转电平； 其他：高阻态。
  [15] reserved ro — 保留。
  [14:12] rg_ocb_evtb2_inc rw — EMEVTB2有效且TCCNT计数方向递增时，APTx_PWMB的输出状态。 000：不做任何动作； 001：低电平； 010：高电平； 011：锁定电平； 100：翻转电平； 其他：高阻态。
  [11:9] rg_ocb_evtb1_inc rw — EMEVTB1有效且TCCNT计数方向递增时，APTx_PWMB的输出状态。 000：不做任何动作； 001：低电平； 010：高电平； 011：锁定电平； 100：翻转电平； 其他：高阻态。
  [8:6] rg_ocb_evta2_inc rw — EMEVTA2有效且TCCNT计数方向递增时，APTx_PWMB的输出状态。 000：不做任何动作； 001：低电平； 010：高电平； 011：锁定电平； 100：翻转电平； 其他：高阻态。
  [5:3] rg_ocb_evta1_inc rw — EMEVTA1有效且TCCNT计数方向递增时，APTx_PWMB的输出状态。 000：不做任何动作； 001：低电平； 010：高电平； 011：锁定电平； 100：翻转电平； 其他：高阻态。
  [2:0] rg_ocb_evtio_inc rw — TRIP1 ～ TRIP3或TRIP9 ~ TRIP11有效且TCCNT计数方向递增时，APTx_PWMB的输出状态。 000：不做任何动作； 001：低电平； 010：高电平； 011：锁定电平； 100：翻转电平； 其他：高阻态。
0x320 OC_EVT_FLAG — OC_EVT_FLAG为故障信号和事件中断标志寄存器。
  [31] rg_int_clr_evt rw write-1-clears — 事件中断APTxEVTINT的中断清除位，写1清0。 0：写0无效； 1：写1有效。
  [30:28] reserved ro — 保留。
  [27] rg_oc_clr_evtb2 rw write-1-clears — EMEVTB2故障信号标志的清除位，写1清0。 0：写0无效； 1：写1有效。
  [26] rg_oc_clr_evtb1 rw write-1-clears — EMEVTB1故障信号标志的清除位，写1清0。 0：写0无效； 1：写1有效。
  [25] rg_oc_clr_evta2 rw write-1-clears — EMEVTA2故障信号标志的清除位，写1清0。 0：写0无效； 1：写1有效。
  [24] rg_oc_clr_evta1 rw write-1-clears — EMEVTA1故障信号标志的清除位，写1清0。 0：写0无效； 1：写1有效。
  [23] reserved ro — 保留。
  [22] rg_oc_clr_evts3 rw write-1-clears — TRIP11故障信号标志的清除位，写1清0。 0：写0无效； 1：写1有效。
  [21] rg_oc_clr_evts2 rw write-1-clears — TRIP10故障信号标志的清除位，写1清0。 0：写0无效； 1：写1有效。
  [20] rg_oc_clr_evts1 rw write-1-clears — TRIP9故障信号标志的清除位，写1清0。 0：写0无效； 1：写1有效。
  [19] reserved ro — 保留。
  [18] rg_oc_clr_evt3 rw write-1-clears — TRIP3故障信号标志的清除位，写1清0。 0：写0无效； 1：写1有效。
  [17] rg_oc_clr_evt2 rw write-1-clears — TRIP2故障信号标志的清除位，写1清0。 0：写0无效； 1：写1有效。
  [16] rg_oc_clr_evt1 rw write-1-clears — TRIP1故障信号标志的清除位，写1清0。 0：写0无效； 1：写1有效。
  [15] ro_int_flag_evt ro — 事件中断APTxEVTINT的中断标志位。 0：APTxEVTINT无效； 1：APTxEVTINT有效。
  [14:12] reserved ro — 保留。
  [11] ro_oc_flag_evtb2 ro — EMEVTB2故障信号标志位。 0：EMEVTB2故障信号无效； 1：EMEVTB2故障信号有效。
  [10] ro_oc_flag_evtb1 ro — EMEVTB1故障信号标志位。 0：EMEVTB1故障信号无效； 1：EMEVTB1故障信号有效。
  [9] ro_oc_flag_evta2 ro — EMEVTA2故障信号标志位。 0：EMEVTA2故障信号无效； 1：EMEVTA2故障信号有效。
  [8] ro_oc_flag_evta1 ro — EMEVTA1故障信号标志位。 0：EMEVTA1故障信号无效； 1：EMEVTA1故障信号有效。
  [7] reserved ro — 保留。
  [6] ro_oc_flag_evts3 ro — TRIP11故障信号标志位。 0：TRIP11故障信号无效； 1：TRIP11故障信号有效。
  [5] ro_oc_flag_evts2 ro — TRIP10故障信号标志位。 0：TRIP10故障信号无效； 1：TRIP10故障信号有效。
  [4] ro_oc_flag_evts1 ro — TRIP9故障信号标志位。 0：TRIP9故障信号无效； 1：TRIP9故障信号有效。
  [3] reserved ro — 保留。
  [2] ro_oc_flag_evt3 ro — TRIP3故障信号标志位。 0：TRIP3故障信号无效； 1：TRIP3故障信号有效。
  [1] ro_oc_flag_evt2 ro — TRIP2故障信号标志位。 0：TRIP2故障信号无效； 1：TRIP2故障信号有效。
  [0] ro_oc_flag_evt1 ro — TRIP1故障信号标志位。 0：TRIP1故障信号无效； 1：TRIP1故障信号有效。
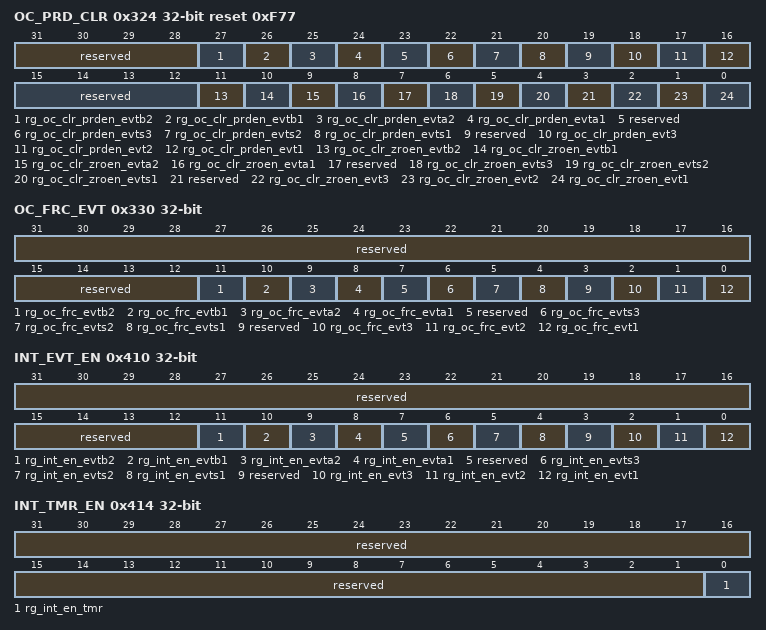
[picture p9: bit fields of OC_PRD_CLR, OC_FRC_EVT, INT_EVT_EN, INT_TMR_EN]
0x324 OC_PRD_CLR reset 0xF77 — OC_PRD_CLR为周期性保护自动清除寄存器。
  [31:28] reserved ro — 保留。
  [27] rg_oc_clr_prden_evtb2 rw — 当EMEVTB2设置成周期性保护时，选择是否在CNT_PRD有效时清除对APTx_PWMA/APTx_PWMB的保护。 0：不使能； 1：使能。
  [26] rg_oc_clr_prden_evtb1 rw — 当EMEVTB1设置成周期性保护时，选择是否在CNT_PRD有效时清除对APTx_PWMA/APTx_PWMB的保护。 0：不使能； 1：使能。
  [25] rg_oc_clr_prden_evta2 rw — 当EMEVTA2设置成周期性保护时，选择是否在CNT_PRD有效时清除对APTx_PWMA/APTx_PWMB的保护。 0：不使能； 1：使能。
  [24] rg_oc_clr_prden_evta1 rw — 当EMEVTA1设置成周期性保护时，选择是否在CNT_PRD有效时清除对APTx_PWMA/APTx_PWMB的保护。 0：不使能； 1：使能。
  [23] reserved ro — 保留。
  [22] rg_oc_clr_prden_evts3 rw — 当TRIP11设置成周期性保护时，选择是否在CNT_PRD有效时清除对APTx_PWMA/APTx_PWMB的保护。 0：不使能； 1：使能。
  [21] rg_oc_clr_prden_evts2 rw — 当TRIP10设置成周期性保护时，选择是否在CNT_PRD有效时清除对APTx_PWMA/APTx_PWMB的保护。 0：不使能； 1：使能。
  [20] rg_oc_clr_prden_evts1 rw — 当TRIP9设置成周期性保护时，选择是否在CNT_PRD有效时清除对APTx_PWMA/APTx_PWMB的保护。 0：不使能； 1：使能。
  [19] reserved ro — 保留。
  [18] rg_oc_clr_prden_evt3 rw — 当TRIP3设置成周期性保护时，选择是否在CNT_PRD有效时清除对APTx_PWMA/APTx_PWMB的保护。 0：不使能； 1：使能。
  [17] rg_oc_clr_prden_evt2 rw — 当TRIP2设置成周期性保护时，选择是否在CNT_PRD有效时清除对APTx_PWMA/APTx_PWMB的保护。 0：不使能； 1：使能。
  [16] rg_oc_clr_prden_evt1 rw — 当TRIP1设置成周期性保护时，选择是否在CNT_PRD有效时清除对APTx_PWMA/APTx_PWMB的保护。 0：不使能； 1：使能。
  [15:12] reserved ro — 保留。
  [11] rg_oc_clr_zroen_evtb2 rw — 当EMEVTB2设置成周期性保护时，选择是否在CNT_ZERO有效时清除对APTx_PWMA/APTx_PWMB的保护。 0：不使能； 1：使能。
  [10] rg_oc_clr_zroen_evtb1 rw — 当EMEVTB1设置成周期性保护时，选择是否在CNT_ZERO有效时清除对APTx_PWMA/APTx_PWMB的保护。 0：不使能； 1：使能。
  [9] rg_oc_clr_zroen_evta2 rw — 当EMEVTA2设置成周期性保护时，选择是否在CNT_ZERO有效时清除对APTx_PWMA/APTx_PWMB的保护。 0：不使能； 1：使能。
  [8] rg_oc_clr_zroen_evta1 rw — 当EMEVTA1设置成周期性保护时，选择是否在CNT_ZERO有效时清除对APTx_PWMA/APTx_PWMB的保护。 0：不使能； 1：使能。
  [7] reserved ro — 保留。
  [6] rg_oc_clr_zroen_evts3 rw — 当TRIP11设置成周期性保护时，选择是否在CNT_ZERO有效时清除对APTx_PWMA/APTx_PWMB的保护。 0：不使能； 1：使能。
  [5] rg_oc_clr_zroen_evts2 rw — 当TRIP10设置成周期性保护时，选择是否在CNT_ZERO有效时清除对APTx_PWMA/APTx_PWMB的保护。 0：不使能； 1：使能。
  [4] rg_oc_clr_zroen_evts1 rw — 当TRIP9设置成周期性保护时，选择是否在CNT_ZERO有效时清除对APTx_PWMA/APTx_PWMB的保护。 0：不使能； 1：使能。
  [3] reserved ro — 保留。
  [2] rg_oc_clr_zroen_evt3 rw — 当TRIP3设置成周期性保护时，选择是否在CNT_ZERO有效时清除对APTx_PWMA/APTx_PWMB的保护。 0：不使能； 1：使能。
  [1] rg_oc_clr_zroen_evt2 rw — 当TRIP2设置成周期性保护时，选择是否在CNT_ZERO有效时清除对APTx_PWMA/APTx_PWMB的保护。 0：不使能； 1：使能。
  [0] rg_oc_clr_zroen_evt1 rw — 当TRIP1设置成周期性保护时，选择是否在CNT_ZERO有效时清除对APTx_PWMA/APTx_PWMB的保护。 0：不使能； 1：使能。
0x330 OC_FRC_EVT — OC_FRC_EVT为强制产生故障信号寄存器。
  [31:12] reserved ro — 保留。
  [11] rg_oc_frc_evtb2 rw — 强制产生EMEVTB2故障信号。 0：无效； 1：有效。
  [10] rg_oc_frc_evtb1 rw — 强制产生EMEVTB1故障信号。 0：无效； 1：有效。
  [9] rg_oc_frc_evta2 rw — 强制产生EMEVTA2故障信号。 0：无效； 1：有效。
  [8] rg_oc_frc_evta1 rw — 强制产生EMEVTA1故障信号。 0：无效； 1：有效。
  [7] reserved ro — 保留。
  [6] rg_oc_frc_evts3 rw — 强制产生TRIP11故障信号。 0：无效； 1：有效。
  [5] rg_oc_frc_evts2 rw — 强制产生TRIP10故障信号。 0：无效； 1：有效。
  [4] rg_oc_frc_evts1 rw — 强制产生TRIP9故障信号。 0：无效； 1：有效。
  [3] reserved ro — 保留。
  [2] rg_oc_frc_evt3 rw — 强制产生TRIP3故障信号。 0：无效； 1：有效。
  [1] rg_oc_frc_evt2 rw — 强制产生TRIP2故障信号。 0：无效； 1：有效。
  [0] rg_oc_frc_evt1 rw — 强制产生TRIP1故障信号。 0：无效； 1：有效。
0x410 INT_EVT_EN — INT_EVT_EN为事件中断使能寄存器。
  [31:12] reserved ro — 保留。
  [11] rg_int_en_evtb2 rw — EMEVTB2触发事件中断的使能位，选择故障信号EMEVTB2有效时，是否产生事件中断APTxEVTINT。 0：不使能； 1：使能。
  [10] rg_int_en_evtb1 rw — EMEVTB1触发事件中断的使能位，选择故障信号EMEVTB1有效时，是否产生事件中断APTxEVTINT。 0：不使能； 1：使能。
  [9] rg_int_en_evta2 rw — EMEVTA2触发事件中断的使能位，选择故障信号EMEVTA2有效时，是否产生事件中断APTxEVTINT。 0：不使能； 1：使能。
  [8] rg_int_en_evta1 rw — EMEVTA1触发事件中断的使能位，选择故障信号EMEVTA1有效时，是否产生事件中断APTxEVTINT。 0：不使能； 1：使能。
  [7] reserved ro — 保留。
  [6] rg_int_en_evts3 rw — TRIP11触发事件中断的使能位，选择故障信号TRIP11有效时，是否产生事件中断APTxEVTINT。 0：不使能； 1：使能。
  [5] rg_int_en_evts2 rw — TRIP10触发事件中断的使能位，选择故障信号TRIP10有效时，是否产生事件中断APTxEVTINT。 0：不使能； 1：使能。
  [4] rg_int_en_evts1 rw — TRIP9触发事件中断的使能位，选择故障信号TRIP9有效时，是否产生事件中断APTxEVTINT。 0：不使能； 1：使能。
  [3] reserved ro — 保留。
  [2] rg_int_en_evt3 rw — TRIP3触发事件中断的使能位，选择故障信号TRIP3有效时，是否产生事件中断APTxEVTINT。 0：不使能； 1：使能。
  [1] rg_int_en_evt2 rw — TRIP2触发事件中断的使能位，选择故障信号TRIP2有效时，是否产生事件中断APTxEVTINT。 0：不使能； 1：使能。
  [0] rg_int_en_evt1 rw — TRIP1触发事件中断的使能位，选择故障信号TRIP1有效时，是否产生事件中断APTxEVTINT。 0：不使能； 1：使能。
0x414 INT_TMR_EN — INT_TMR_EN为定时中断使能寄存器。
  [31:1] reserved ro — 保留。
  [0] rg_int_en_tmr rw — 定时中断APTxTMRINT的使能位。 0：不使能； 1：使能。
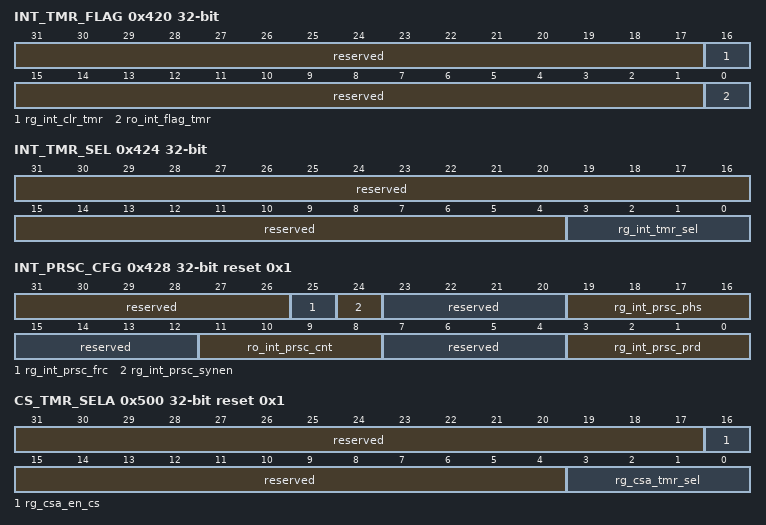
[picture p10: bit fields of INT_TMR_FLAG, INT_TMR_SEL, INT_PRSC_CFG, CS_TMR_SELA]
0x420 INT_TMR_FLAG — INT_TMR_FLAG为定时中断标志寄存器。
  [31:17] reserved ro — 保留。
  [16] rg_int_clr_tmr rw write-1-clears — 定时中断APTxTMRINT的中断清除位，写1清0。 0：写0无效； 1：写1有效。
  [15:1] reserved ro — 保留。
  [0] ro_int_flag_tmr ro — 定时中断APTxTMRINT的中断标志位。 0：APTxTMRINT无效； 1：APTxTMRINT有效。
0x424 INT_TMR_SEL — INT_TMR_SEL为定时中断的触发源选择寄存器。
  [31:4] reserved ro — 保留。
  [3:0] rg_int_tmr_sel rw — 定时中断APTxTMRINT的触发源选择。 0x1：CNT_ZERO有效； 0x2：CNT_PRD有效； 0x3：CNT_ZRO或CNT_PRD有效； 0x4：CNT_REFA有效且TCCNT计数方向递增； 0x5：CNT_REFA有效且TCCNT计数方向递减； 0x6：CNT_REFB有效且TCCNT计数方向递增； 0x7：CNT_REFB有效且TCCNT计数方向递减； 0x8：CNT_REFC有效且TCCNT计数方向递增； 0x9：CNT_REFC有效且TCCNT计数方向递减； 0xA：CNT_REFD有效且TCCNT计数方向递增； 0xB：CNT_REFD有效且TCCNT计数方向递减； 其他：保留。
0x428 INT_PRSC_CFG reset 0x1 — INT_PRSC_CFG为定时中断缩减配置寄存器。
  [31:26] reserved ro — 保留。
  [25] rg_int_prsc_frc rw write-1-clears — 定时中断缩减计数器强制加1。 0：写0无效； 1：写1有效。
  [24] rg_int_prsc_synen rw — 定时中断缩减计数器的同步使能。 0：不使能； 1：使能。
  [23:20] reserved ro — 保留。
  [19:16] rg_int_prsc_phs rw — 定时中断缩减计数器的同步值。
  [15:12] reserved ro — 保留。
  [11:8] ro_int_prsc_cnt ro — 定时中断缩减计数器的计数值。
  [7:4] reserved ro — 保留。
  [3:0] rg_int_prsc_prd rw — 定时中断的缩减比例。 0x1：每发生1次有效的定时中断触发源，就产生定时中断； 0x2：每发生2次有效的定时中断触发源，就产生定时中断； 0x3：每发生3次有效的定时中断触发源，就产生定时中断； … 0xF：每发生15次有效的定时中断触发源，就产生定时中断。 其他：保留。
0x500 CS_TMR_SELA reset 0x1 — CS_TMR_SELA为APTxSOCA的触发源选择寄存器。
  [31:17] reserved ro — 保留。
  [16] rg_csa_en_cs rw — APTxSOCA的使能位。 0：不使能； 1：使能。
  [15:4] reserved ro — 保留。
  [3:0] rg_csa_tmr_sel rw — APTxSOCA的触发源选择。 0x0：EMEVTA1有效； 0x1：CNT_ZERO有效； 0x2：CNT_PRD有效； 0x3：CNT_ZERO或CNT_PRD有效； 0x4：CNT_REFA有效且TCCNT计数方向递增； 0x5：CNT_REFA有效且TCCNT计数方向递减； 0x6：CNT_REFB有效且TCCNT计数方向递增； 0x7：CNT_REFB有效且TCCNT计数方向递减； 0x8：CNT_REFC有效且TCCNT计数方向递增； 0x9：CNT_REFC有效且TCCNT计数方向递减； 0xA：CNT_REFD有效且TCCNT计数方向递增； 0xB：CNT_REFD有效且TCCNT计数方向递减； 其他：保留。
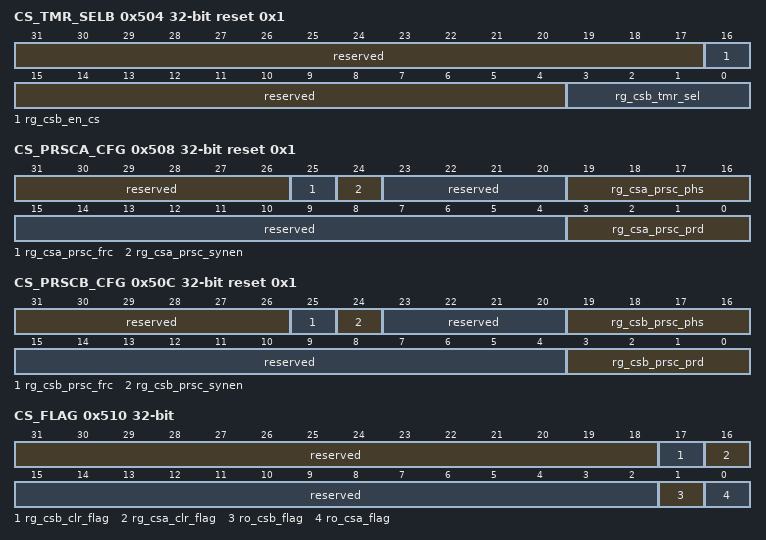
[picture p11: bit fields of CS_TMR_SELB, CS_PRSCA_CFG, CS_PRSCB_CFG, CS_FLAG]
0x504 CS_TMR_SELB reset 0x1 — CS_TMR_SELB为APTxSOCB的触发源选择寄存器。
  [31:17] reserved ro — 保留。
  [16] rg_csb_en_cs rw — APTxSOCB的使能位。 0：不使能； 1：使能。
  [15:4] reserved ro — 保留。
  [3:0] rg_csb_tmr_sel rw — APTxSOCB的触发源选择。 0x0：EMEVTB1有效； 0x1：CNT_ZERO有效； 0x2：CNT_PRD有效； 0x3：CNT_ZERO或CNT_PRD有效； 0x4：CNT_REFA有效且TCCNT计数方向递增； 0x5：CNT_REFA有效且TCCNT计数方向递减； 0x6：CNT_REFB有效且TCCNT计数方向递增； 0x7：CNT_REFB有效且TCCNT计数方向递减； 0x8：CNT_REFC有效且TCCNT计数方向递增； 0x9：CNT_REFC有效且TCCNT计数方向递减； 0xA：CNT_REFD有效且TCCNT计数方向递增； 0xB：CNT_REFD有效且TCCNT计数方向递减； 其他：保留。
0x508 CS_PRSCA_CFG reset 0x1 — CS_PRSCA_CFG为APTxSOCA缩减配置寄存器。
  [31:26] reserved ro — 保留。
  [25] rg_csa_prsc_frc rw write-1-clears — APTxSOCA缩减计数器强制加1。 0：写0无效； 1：写1有效。
  [24] rg_csa_prsc_synen rw — APTxSOCA缩减计数器的同步使能。 0：不使能； 1：使能。
  [23:20] reserved ro — 保留。
  [19:16] rg_csa_prsc_phs rw — APTxSOCA缩减计数器的同步值。
  [15:4] reserved ro — 保留。
  [3:0] rg_csa_prsc_prd rw — APTxSOCA的缩减比例。 0x1：每发生1次有效的APTxSOCA的触发源，就产生APTxSOCA； 0x2：每发生2次有效的APTxSOCA的触发源，就产生APTxSOCA； 0x3：每发生3次有效的APTxSOCA的触发源，就产生APTxSOCA； … 0xF：每发生15次有效的APTxSOCA的触发源，就产生APTxSOCA。 其他：保留。
0x50C CS_PRSCB_CFG reset 0x1 — CS_PRSCB_CFG为APTxSOCB缩减配置寄存器。
  [31:26] reserved ro — 保留。
  [25] rg_csb_prsc_frc rw write-1-clears — APTxSOCB缩减计数器强制加1。 0：写0无效； 1：写1有效。
  [24] rg_csb_prsc_synen rw — APTxSOCB缩减计数器的同步使能。 0：不使能； 1：使能。
  [23:20] reserved ro — 保留。
  [19:16] rg_csb_prsc_phs rw — APTxSOCB缩减计数器的同步值。
  [15:4] reserved ro — 保留。
  [3:0] rg_csb_prsc_prd rw — APTxSOCB的缩减比例。 0x1：每发生1次有效的APTxSOCB的触发源，就产生APTxSOCB； 0x2：每发生2次有效的APTxSOCB的触发源，就产生APTxSOCB； 0x3：每发生3次有效的APTxSOCB的触发源，就产生APTxSOCB； … 0xF：每发生15次有效的APTxSOCB的触发源，就产生APTxSOCB。 其他：保留。
0x510 CS_FLAG — CS_FLAG为APTxSOCA/APTxSOCB标志寄存器。
  [31:18] reserved ro — 保留。
  [17] rg_csb_clr_flag rw write-1-clears — APTxSOCB标志清除位，写1清0。 0：写0无效； 1：写1有效。
  [16] rg_csa_clr_flag rw write-1-clears — APTxSOCA标志清除位，写1清0。 0：写0无效； 1：写1有效。
  [15:2] reserved ro — 保留。
  [1] ro_csb_flag ro — APTxSOCB的标志位。 0：没有产生APTxSOCB； 1：已经产生APTxSOCB。
  [0] ro_csa_flag ro — APTxSOCA的标志位。 0：没有产生APTxSOCA； 1：已经产生APTxSOCA。
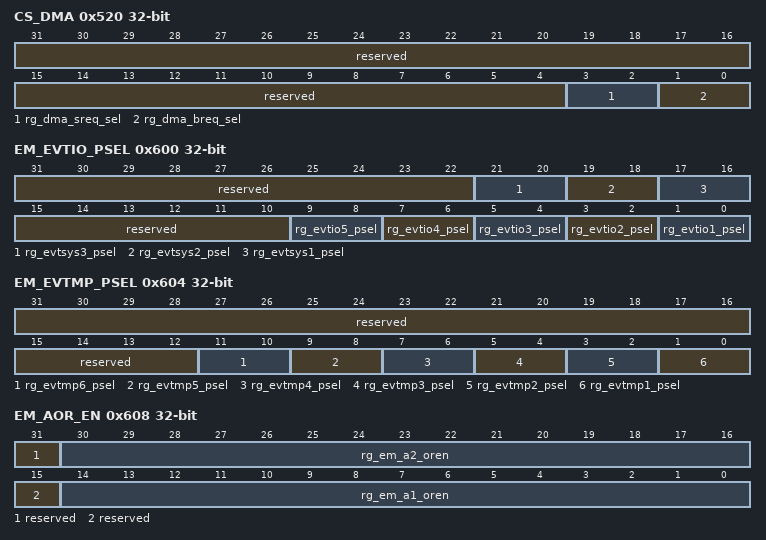
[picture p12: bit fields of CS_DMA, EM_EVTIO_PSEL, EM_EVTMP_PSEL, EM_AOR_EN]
0x520 CS_DMA — CS_DMA为DMA请求配置寄存器。
  [31:4] reserved ro — 保留。
  [3:2] rg_dma_sreq_sel rw — DMA Single请求的触发源选择。 01：TRIGA信号有效； 10：TRIGB信号有效； 其他：禁止产生DMA Single请求。
  [1:0] rg_dma_breq_sel rw — DMA Burst请求的源头选择。 01：TRIGA信号有效； 10：TRIGB信号有效； 其他：禁止产生DMA Burst请求。
0x600 EM_EVTIO_PSEL — EM_EVTIO_PSEL为事件管理极性选择寄存器1。
  [31:22] reserved ro — 保留。
  [21:20] rg_evtsys3_psel rw — TRIP11的极性选择。 00：TRIP11 = sys_mem_fail； 01：TRIP11 = ～sys_mem_fail； 10：TRIP11 = 0； 11：TRIP11 = 1。
  [19:18] rg_evtsys2_psel rw — TRIP10的极性选择。 00：TRIP10 = clock_fail； 01：TRIP10 = ～clock_fail； 10：TRIP10 = 0； 11：TRIP10 = 1。
  [17:16] rg_evtsys1_psel rw — TRIP9的极性选择。 00：TRIP9 = debug_mode； 01：TRIP9 = ～debug_mode； 10：TRIP9 = 0； 11：TRIP9 = 1。
  [15:10] reserved ro — 保留。
  [9:8] rg_evtio5_psel rw — TRIP5的极性选择。 00：TRIP5 = APT_EVTIO5； 01：TRIP5 = ～APT_EVTIO5； 10：TRIP5 = 0； 11：TRIP5 = 1。
  [7:6] rg_evtio4_psel rw — TRIP4的极性选择。 00：TRIP4 = APT_EVTIO4； 01：TRIP4 = ～APT_EVTIO4； 10：TRIP4 = 0； 11：TRIP4 = 1。
  [5:4] rg_evtio3_psel rw — TRIP3的极性选择。 00：TRIP3 = POE2； 01：TRIP3 = ～POE2； 10：TRIP3 = 0； 11：TRIP3 = 1。
  [3:2] rg_evtio2_psel rw — TRIP2的极性选择。 00：TRIP2 = POE1； 01：TRIP2 = ～POE1； 10：TRIP2 = 0； 11：TRIP2 = 1。
  [1:0] rg_evtio1_psel rw — TRIP1的极性选择。 00：TRIP1 = POE0； 01：TRIP1 = ～POE0； 10：TRIP1 = 0； 11：TRIP1 = 1。
0x604 EM_EVTMP_PSEL — EM_EVTMP_PSEL为事件管理极性选择寄存器2。
  [31:12] reserved ro — 保留。
  [11:10] rg_evtmp6_psel rw — TRIP8的极性选择。 00：TRIP8 = APT_EVTMP6； 01：TRIP8 = ～APT_EVTMP6； 10：TRIP8 = 0； 11：TRIP8 = 1。
  [9:8] rg_evtmp5_psel rw — TRIP7的极性选择。 00：TRIP7 = APT_EVTMP5； 01：TRIP7 = ～APT_EVTMP5； 10：TRIP7 = 0； 11：TRIP7 = 1。
  [7:6] rg_evtmp4_psel rw — TRIP6的极性选择。 00：TRIP6 = APT_EVTMP4； 01：TRIP6 = ～APT_EVTMP4； 10：TRIP6 = 0； 11：TRIP6 = 1。
  [5:4] rg_evtmp3_psel rw — TRIP14的极性选择。 00：TRIP14 = ACMP2_OUT； 01：TRIP14 = ～ACMP2_OUT； 10：TRIP14 = 0； 11：TRIP14 = 1。
  [3:2] rg_evtmp2_psel rw — TRIP13的极性选择。 00：TRIP13 = ACMP1_OUT； 01：TRIP13= ～ACMP1_OUT； 10：TRIP13 = 0； 11：TRIP13 = 1。
  [1:0] rg_evtmp1_psel rw — TRIP12的极性选择。 00：TRIP12 = ACMP0_OUT； 01：TRIP12 = ～ACMP0_OUT； 10：TRIP12 = 0； 11：TRIP12 = 1。
0x608 EM_AOR_EN — EM_AOR_EN为事件管理组合输入选择寄存器A。
  [31] reserved ro — 保留。
  [30:16] rg_em_a2_oren rw — TRIP_OR_A2的触发源选择，每个比特对应一个信号。 bit[24]：代表TRIP8的使能位； bit[23]：代表TRIP7的使能位； bit[22]：代表TRIP6的使能位； bit[21]：代表TRIP14的使能位； bit[20]：代表TRIP13的使能位； bit[19]：代表TRIP12的使能位； bit[18]：代表TRIP3的使能位； bit[17]：代表TRIP2的使能位； bit[16]：代表TRIP1的使能位； 其他比特无效，应配置为0。 当相应的比特为1时，代表对应的信号参与逻辑或； 当相应的比特为0时，代表对应的信号不参与逻辑或。
  [15] reserved ro — 保留。
  [14:0] rg_em_a1_oren rw — TRIP_OR_A1的触发源选择，每个比特对应一个信号。 bit[8]：代表TRIP8的使能位； bit[7]：代表TRIP7的使能位； bit[6]：代表TRIP6的使能位； bit[5]：代表TRIP14的使能位； bit[4]：代表TRIP13的使能位； bit[3]：代表TRIP12的使能位； bit[2]：代表TRIP3的使能位； bit[1]：代表TRIP2的使能位； bit[0]：代表TRIP1的使能位； 其他比特无效，应配置为0。 当相应的比特为1时，代表对应的信号参与逻辑或； 当相应的比特为0时，代表对应的信号不参与逻辑或。
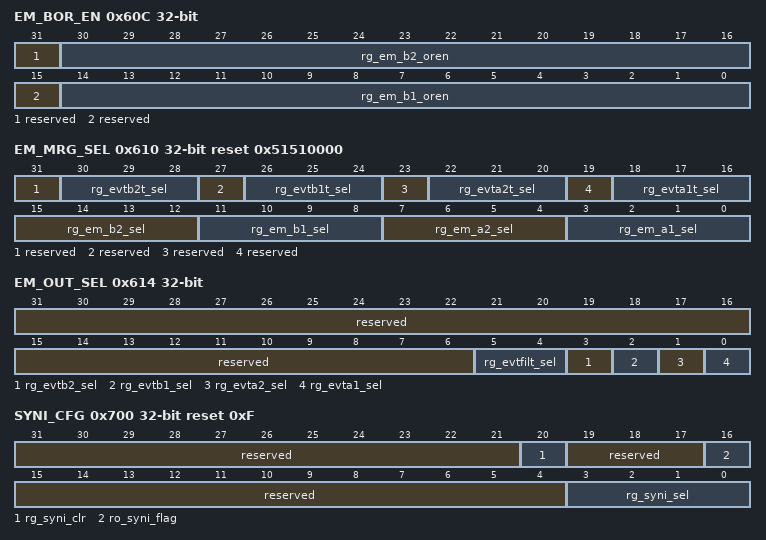
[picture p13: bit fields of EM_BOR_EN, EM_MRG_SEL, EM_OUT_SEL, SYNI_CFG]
0x60C EM_BOR_EN — EM_BOR_EN为事件管理组合输入选择寄存器B。
  [31] reserved ro — 保留。
  [30:16] rg_em_b2_oren rw — TRIP_OR_B2的触发源选择，每个比特对应一个信号。 bit[24]：代表TRIP8的使能位； bit[23]：代表TRIP7的使能位； bit[22]：代表TRIP6的使能位； bit[21]：代表TRIP14的使能位； bit[20]：代表TRIP13的使能位； bit[19]：代表TRIP12的使能位； bit[18]：代表TRIP3的使能位； bit[17]：代表TRIP2的使能位； bit[16]：代表TRIP1的使能位； 其他比特无效，应配置为0。 当相应的比特为1时，代表对应的信号参与逻辑或； 当相应的比特为0时，代表对应的信号不参与逻辑或。
  [15] reserved ro — 保留。
  [14:0] rg_em_b1_oren rw — TRIP_OR_B1的触发源选择，每个比特对应一个信号。 bit[8]：代表TRIP8的使能位； bit[7]：代表TRIP7的使能位； bit[6]：代表TRIP6的使能位； bit[5]：代表TRIP14的使能位； bit[4]：代表TRIP13的使能位； bit[3]：代表TRIP12的使能位； bit[2]：代表TRIP3的使能位； bit[1]：代表TRIP2的使能位； bit[0]：代表TRIP1的使能位； 其他比特无效，应配置为0。 当相应的比特为1时，代表对应的信号参与逻辑或； 当相应的比特为0时，代表对应的信号不参与逻辑或。
0x610 EM_MRG_SEL reset 0x51510000 — EM_MRG_SEL为事件管理输入选择寄存器。
  [31] reserved ro — 保留。
  [30:28] rg_evtb2t_sel rw — EMEVTB2_TEMP有效（高电平有效）的条件选择。 0x1：EMEVTB1_SRC为高电平； 0x2：EMEVTB1_SRC为高电平，且EMEVTB2_SRC为低电平； 0x3：EMEVTB1_SRC为高电平，且EMEVTB2_SRC为高电平； 0x4：EMEVTB1_SRC为低电平，且EMEVTB2_SRC为高电平； 0x5：EMEVTB2_SRC为高电平； 其他：EMEVTB2_TEMP输出低电平。
  [27] reserved ro — 保留。
  [26:24] rg_evtb1t_sel rw — EMEVTB1_TEMP有效（高电平有效）的条件选择。 0x1：EMEVTB1_SRC为高电平； 0x2：EMEVTB1_SRC为高电平，且EMEVTB2_SRC为低电平； 0x3：EMEVTB1_SRC为高电平，且EMEVTB2_SRC为高电平； 0x4：EMEVTB1_SRC为低电平，且EMEVTB2_SRC为高电平； 0x5：EMEVTB2_SRC为高电平； 其他：EMEVTB1_TEMP输出低电平。
  [23] reserved ro — 保留。
  [22:20] rg_evta2t_sel rw — EMEVTA2_TEMP有效（高电平有效）的条件选择。 0x1：EMEVTA1_SRC为高电平； 0x2：EMEVTA1_SRC为高电平，且EMEVTA2_SRC为低电平； 0x3：EMEVTA1_SRC为高电平，且EMEVTA2_SRC为高电平； 0x4：EMEVTA1_SRC为低电平，且EMEVTA2_SRC为高电平； 0x5：EMEVTA2_SRC为高电平； 其他：EMEVTA2_TEMP输出低电平。
  [19] reserved ro — 保留。
  [18:16] rg_evta1t_sel rw — EMEVTA1_TEMP有效（高电平有效）的条件选择。 0x1：EMEVTA1_SRC为高电平； 0x2：EMEVTA1_SRC为高电平，且EMEVTA2_SRC为低电平； 0x3：EMEVTA1_SRC为高电平，且EMEVTA2_SRC为高电平； 0x4：EMEVTA1_SRC为低电平，且EMEVTA2_SRC为高电平； 0x5：EMEVTA2_SRC为高电平； 其他：EMEVTA1_TEMP输出低电平。
  [15:12] rg_em_b2_sel rw — EMEVTB2_SRC触发源选择。 0x0：TRIP1； 0x1：TRIP2； 0x2：TRIP3； 0x3：TRIP12； 0x6：TRIP6； 0x7：TRIP7； 0x8：TRIP8； 0xF：TRIP_OR_B2； 其他：TRIP1。
  [11:8] rg_em_b1_sel rw — EMEVTB1_SRC触发源选择。 0x0：TRIP1； 0x1：TRIP2； 0x2：TRIP3； 0x3：TRIP12； 0x6：TRIP6； 0x7：TRIP7； 0x8：TRIP8； 0xF：TRIP_OR_B1； 其他：TRIP1。
  [7:4] rg_em_a2_sel rw — EMEVTA2_SRC触发源选择。 0x0：TRIP1； 0x1：TRIP2； 0x2：TRIP3； 0x3：TRIP12； 0x6：TRIP6； 0x7：TRIP7； 0x8：TRIP8； 0xF：TRIP_OR_A2； 其他：TRIP1。
  [3:0] rg_em_a1_sel rw — EMEVTA1_SRC触发源选择。 0x0：TRIP1； 0x1：TRIP2； 0x2：TRIP3； 0x3：TRIP12； 0x6：TRIP6； 0x7：TRIP7； 0x8：TRIP8； 0xF：TRIP_OR_A1； 其他：TRIP1。
0x614 EM_OUT_SEL — EM_OUT_SEL为事件管理输出选择寄存器。
  [31:6] reserved ro — 保留。
  [5:4] rg_evtfilt_sel rw — EMEVTFILT的触发源选择。 00：EMEVTA1_TEMP； 01：EMEVTA2_TEMP； 10：EMEVTB1_TEMP； 11：EMEVTB2_TEMP。
  [3] rg_evtb2_sel rw — EMEVTB2的触发源选择。 0：EMEVTB2_TEMP； 1：EMEVTFILT。
  [2] rg_evtb1_sel rw — EMEVTB1的触发源选择。 0：EMEVTB1_TEMP； 1：EMEVTFILT。
  [1] rg_evta2_sel rw — EMEVTA2的触发源选择。 0：EMEVTA2_TEMP； 1：EMEVTFILT。
  [0] rg_evta1_sel rw — EMEVTA1的触发源选择。 0：EMEVTA1_TEMP； 1：EMEVTFILT。
0x700 SYNI_CFG reset 0xF — SYNI_CFG为同步输入配置寄存器。
  [31:21] reserved ro — 保留。
  [20] rg_syni_clr rw write-1-clears — APTxSYNCI的标志清除位，写1清0。 0：写0无效； 1：写1清除APTxSYNCI的标志位ro_syni_flag。
  [19:17] reserved ro — 保留。
  [16] ro_syni_flag ro — APTxSYNCI的标志位。 0：APTxSYNCI无效； 1：APTxSYNCI有效。
  [15:4] reserved ro — 保留。
  [3:0] rg_syni_sel rw — APTxSYNCI的触发源选择。 0x0：APT0SYNCO； 0x1：APT1SYNCO； 0x2：APT2SYNCO； 0x3：APT3SYNCO； 0x4：APT4SYNCO； 0x5：APT5SYNCO； 0x6：APT6SYNCO； 0x7：APT7SYNCO； 0x8：APT8SYNCO； 0x9：CAPM0SYNCO； 0xA：CAPM1SYNCO； 0xB：CAPM2SYNCO； 0xC：TRIP4； 0xD：TRIP5； 其他：禁止产生APTxSYNCI。
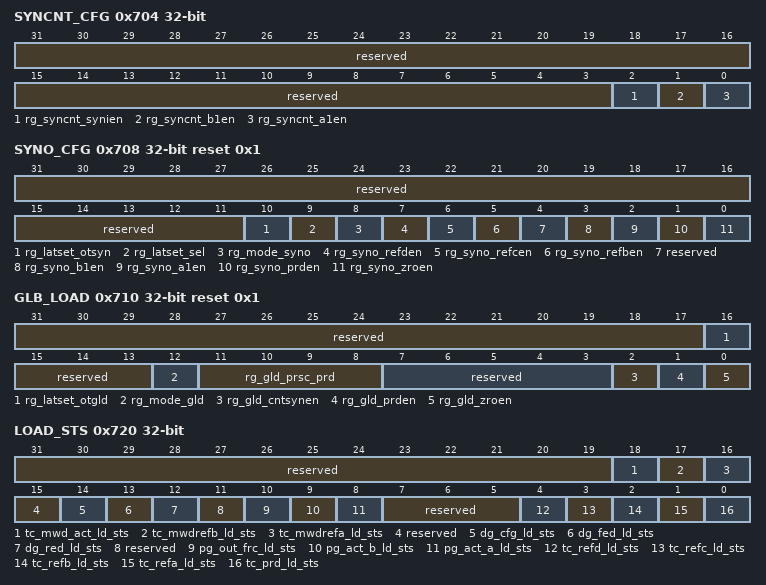
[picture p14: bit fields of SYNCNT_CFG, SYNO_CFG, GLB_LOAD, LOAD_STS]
0x704 SYNCNT_CFG — SYNCNT_CFG为计数器同步信号配置寄存器。
  [31:3] reserved ro — 保留。
  [2] rg_syncnt_synien rw — 当APTxSYNCI有效时，选择是否产生APTCNTSYNC。 0：不使能； 1：使能。
  [1] rg_syncnt_b1en rw — 当EMEVTB1有效时，选择是否产生APTCNTSYNC。 0：不使能； 1：使能。
  [0] rg_syncnt_a1en rw — 当EMEVTA1有效时，选择是否产生APTCNTSYNC。 0：不使能； 1：使能。
0x708 SYNO_CFG reset 0x1 — SYNO_CFG为同步输出配置寄存器。
  [31:11] reserved ro — 保留。
  [10] rg_latset_otsyn rw write-1-clears — 控制同步输出单次锁存器置位。 0：写0无效； 1：写1有效。
  [9] rg_latset_sel rw — 当选择单次同步输出模式，选择同步输出单次锁存器置位的条件。 0：向SYNO_CFG[rg_latset_otsyn]写1时置位； 1：向GLB_LOAD[rg_latset_otgld]写1时置位。
  [8] rg_mode_syno rw — 同步输出的模式选择。 0：单次同步输出； 1：不限次数同步输出。
  [7] rg_syno_refden rw — 当CNT_REFD有效时，选择是否产生APTxSYNCO。 0：不使能； 1：使能。
  [6] rg_syno_refcen rw — 当CNT_REFC有效时，选择是否产生APTxSYNCO。 0：不使能； 1：使能。
  [5] rg_syno_refben rw — 当CNT_REFB有效时，选择是否产生APTxSYNCO。 0：不使能； 1：使能。
  [4] reserved ro — 保留。
  [3] rg_syno_b1en rw — 当EMEVTB1有效时，选择是否产生APTxSYNCO。 0：不使能； 1：使能。
  [2] rg_syno_a1en rw — 当EMEVTA1有效时，选择是否产生APTxSYNCO。 0：不使能； 1：使能。
  [1] rg_syno_prden rw — 当CNT_PRD有效时，选择是否产生APTxSYNCO。 0：不使能； 1：使能。
  [0] rg_syno_zroen rw — 当CNT_ZERO有效时，选择是否产生APTxSYNCO。 0：不使能； 1：使能。
0x710 GLB_LOAD reset 0x1 — GLB_LOAD为全局加载配置寄存器。
  [31:17] reserved ro — 保留。
  [16] rg_latset_otgld rw write-1-clears — 控制全局加载单次锁存器置位。 0：写0无效； 1：写1有效。
  [15:13] reserved ro — 保留。
  [12] rg_mode_gld rw — 全局加载的模式选择。 0：单次加载； 1：不限次数加载。
  [11:8] rg_gld_prsc_prd rw — 全局加载信号缩减计数器的缩减比例。 0x1：每发生1次有效的全局加载触发信号，就产生glb_ld； 0x2：每发生2次有效的全局加载触发信号，就产生glb_ld； 0x3：每发生3次有效的全局加载触发信号，就产生glb_ld； … 0xF：每发生15次有效的全局加载触发信号，就产生glb_ld。 其他：保留。
  [7:3] reserved ro — 保留。
  [2] rg_gld_cntsynen rw — 使能APTCNTSYNC作为全局加载触发信号。 0：不使能； 1：使能。
  [1] rg_gld_prden rw — 使能CNT_PRD作为全局加载触发信号。 0：不使能； 1：使能。
  [0] rg_gld_zroen rw — 使能CNT_ZERO作为全局加载触发信号。 0：不使能； 1：使能。
0x720 LOAD_STS ro — LOAD_STS为缓存状态寄存器。
  [31:19] reserved — 保留。
  [18] tc_mwd_act_ld_sts — 当使能了TC_MWD_ACT寄存器的缓存，指示寄存器的缓存状态。 0：缓存寄存器空； 1：缓存寄存器满。
  [17] tc_mwdrefb_ld_sts — 当使能了TC_MWDREFB寄存器的缓存，指示寄存器的缓存状态。 0：缓存寄存器空； 1：缓存寄存器满。
  [16] tc_mwdrefa_ld_sts — 当使能了TC_MWDREFA寄存器的缓存，指示寄存器的缓存状态。 0：缓存寄存器空； 1：缓存寄存器满。
  [15] reserved — 保留。
  [14] dg_cfg_ld_sts — 当使能了DG_CFG寄存器的缓存，指示寄存器的缓存状态。 0：缓存寄存器空； 1：缓存寄存器满。
  [13] dg_fed_ld_sts — 当使能了DG_FEG寄存器的缓存，指示DG_FEG寄存器的缓存状态。 0：缓存寄存器空； 1：缓存寄存器满。
  [12] dg_red_ld_sts — 当使能了DG_REG寄存器的缓存，指示DG_REG寄存器的缓存状态。 0：缓存寄存器空； 1：缓存寄存器满。
  [11] reserved — 保留。
  [10] pg_out_frc_ld_sts — 当使能了PG_OUT_FRC寄存器的缓存，指示寄存器的缓存状态。 0：缓存寄存器空； 1：缓存寄存器满。
  [9] pg_act_b_ld_sts — 当使能了PG_ACT_B寄存器的缓存，指示寄存器的缓存状态。 0：缓存寄存器空； 1：缓存寄存器满。
  [8] pg_act_a_ld_sts — 当使能了PG_ACT_A寄存器的缓存，指示寄存器的缓存状态。 0：缓存寄存器空； 1：缓存寄存器满。
  [7:5] reserved — 保留。
  [4] tc_refd_ld_sts — 当使能了TC_REFD寄存器的缓存，指示寄存器的缓存状态。 0：缓存寄存器空； 1：缓存寄存器满。
  [3] tc_refc_ld_sts — 当使能了TC_REFC寄存器的缓存，指示寄存器的缓存状态。 0：缓存寄存器空； 1：缓存寄存器满。
  [2] tc_refb_ld_sts — 当使能了TC_REFB寄存器的缓存，指示寄存器的缓存状态。 0：缓存寄存器空； 1：缓存寄存器满。
  [1] tc_refa_ld_sts — 当使能了TC_REFA寄存器的缓存，指示寄存器的缓存状态。 0：缓存寄存器空； 1：缓存寄存器满。
  [0] tc_prd_ld_sts — 当使能了TC_PRD寄存器的缓存，指示寄存器的缓存状态。 0：缓存寄存器空； 1：缓存寄存器满。
0x730 SYN_FRC — SYN_FRC为软件强制寄存器。
  [31:29] reserved ro — 保留。
  [28] rg_synpg_frc rw write-1-clears — 强制产生一个PG_ACT_A/PG_ACT_B寄存器的独立加载的触发信号。 0：写0无效； 1：写1有效。
  [27:25] reserved ro — 保留。
  [24] rg_int_syn_frc rw write-1-clears — 强制定时中断缩减计数器更新成INT_PRSC_CFG[rg_int_prsc_phs]中的值。 0：写0无效； 1：写1有效。
  [23:22] reserved ro — 保留。
  [21] rg_csb_syn_frc rw write-1-clears — 强制产生一次APTxSOCB的触发源。 0：写0无效； 1：写1有效。
  [20] rg_csa_syn_frc rw write-1-clears — 强制产生一次APTxSOCA的触发源。 0：写0无效； 1：写1有效。
  [19:13] reserved ro — 保留。
  [12] rg_gld_frc rw write-1-clears — 强制产生一次全局加载信号的触发信号。 0：写0无效； 1：写1有效。
  [11:5] reserved ro — 保留。
  [4] rg_syno_frc rw write-1-clears — 强制产生一次APTxSYNCO的触发源。 0：写0无效； 1：写1有效。
  [3:1] reserved ro — 保留。
  [0] rg_syncnt_frc rw write-1-clears — 强制产生一个APTCNTSYNC信号。 0：写0无效； 1：写1有效。
0x800 PWM_STATUS ro reset 0x101 — PWM_STATUS为PWM输出状态寄存器。
  [31:10] reserved — 保留。
  [9] ro_pwmb_status — APT_PWMB输出状态，只有当PWM_STATUS[ro_pwmb_oen_status]为0时，该位域的值才有效。 0：APT_PWMB输出为低电平； 1：APT_PWMB输出为高电平。
  [8] ro_pwmb_oen_status — APT_PWMB_OEN输出状态。 0：APT_PWMB输出状态查询PWM_STATUS[ro_pwmb_status]位域； 1：APT_PWMB输出为高阻态。
  [7:2] reserved — 保留。
  [1] ro_pwma_status — APT_PWMA输出状态，只有当PWM_STATUS[ro_pwma_oen_status]为0时，该位域的值才有效。 0：APT_PWMA输出为低电平； 1：APT_PWMA输出为高电平。
  [0] ro_pwma_oen_status — APT_PWMA_OEN输出状态。 0：APT_PWMA输出状态查询PWM_STATUS[ro_pwma_status]位域； 1：APT_PWMA输出为高阻态。
0x804 APT_POE_FLAG ro — APT_POE_FLAG为POE事件标志寄存器。
  [31:3] reserved — 保留。
  [2] ro_poe2_flag — POE2事件标志。 0：APT的输入POE2事件为低电平； 1：APT的输入POE2事件为高电平。
  [1] ro_poe1_flag — POE1事件标志。 0：APT的输入POE1事件为低电平； 1：APT的输入POE1事件为高电平。
  [0] ro_poe0_flag — POE0事件标志。 0：APT的输入POE0事件为低电平； 1：APT的输入POE0事件为高电平。
